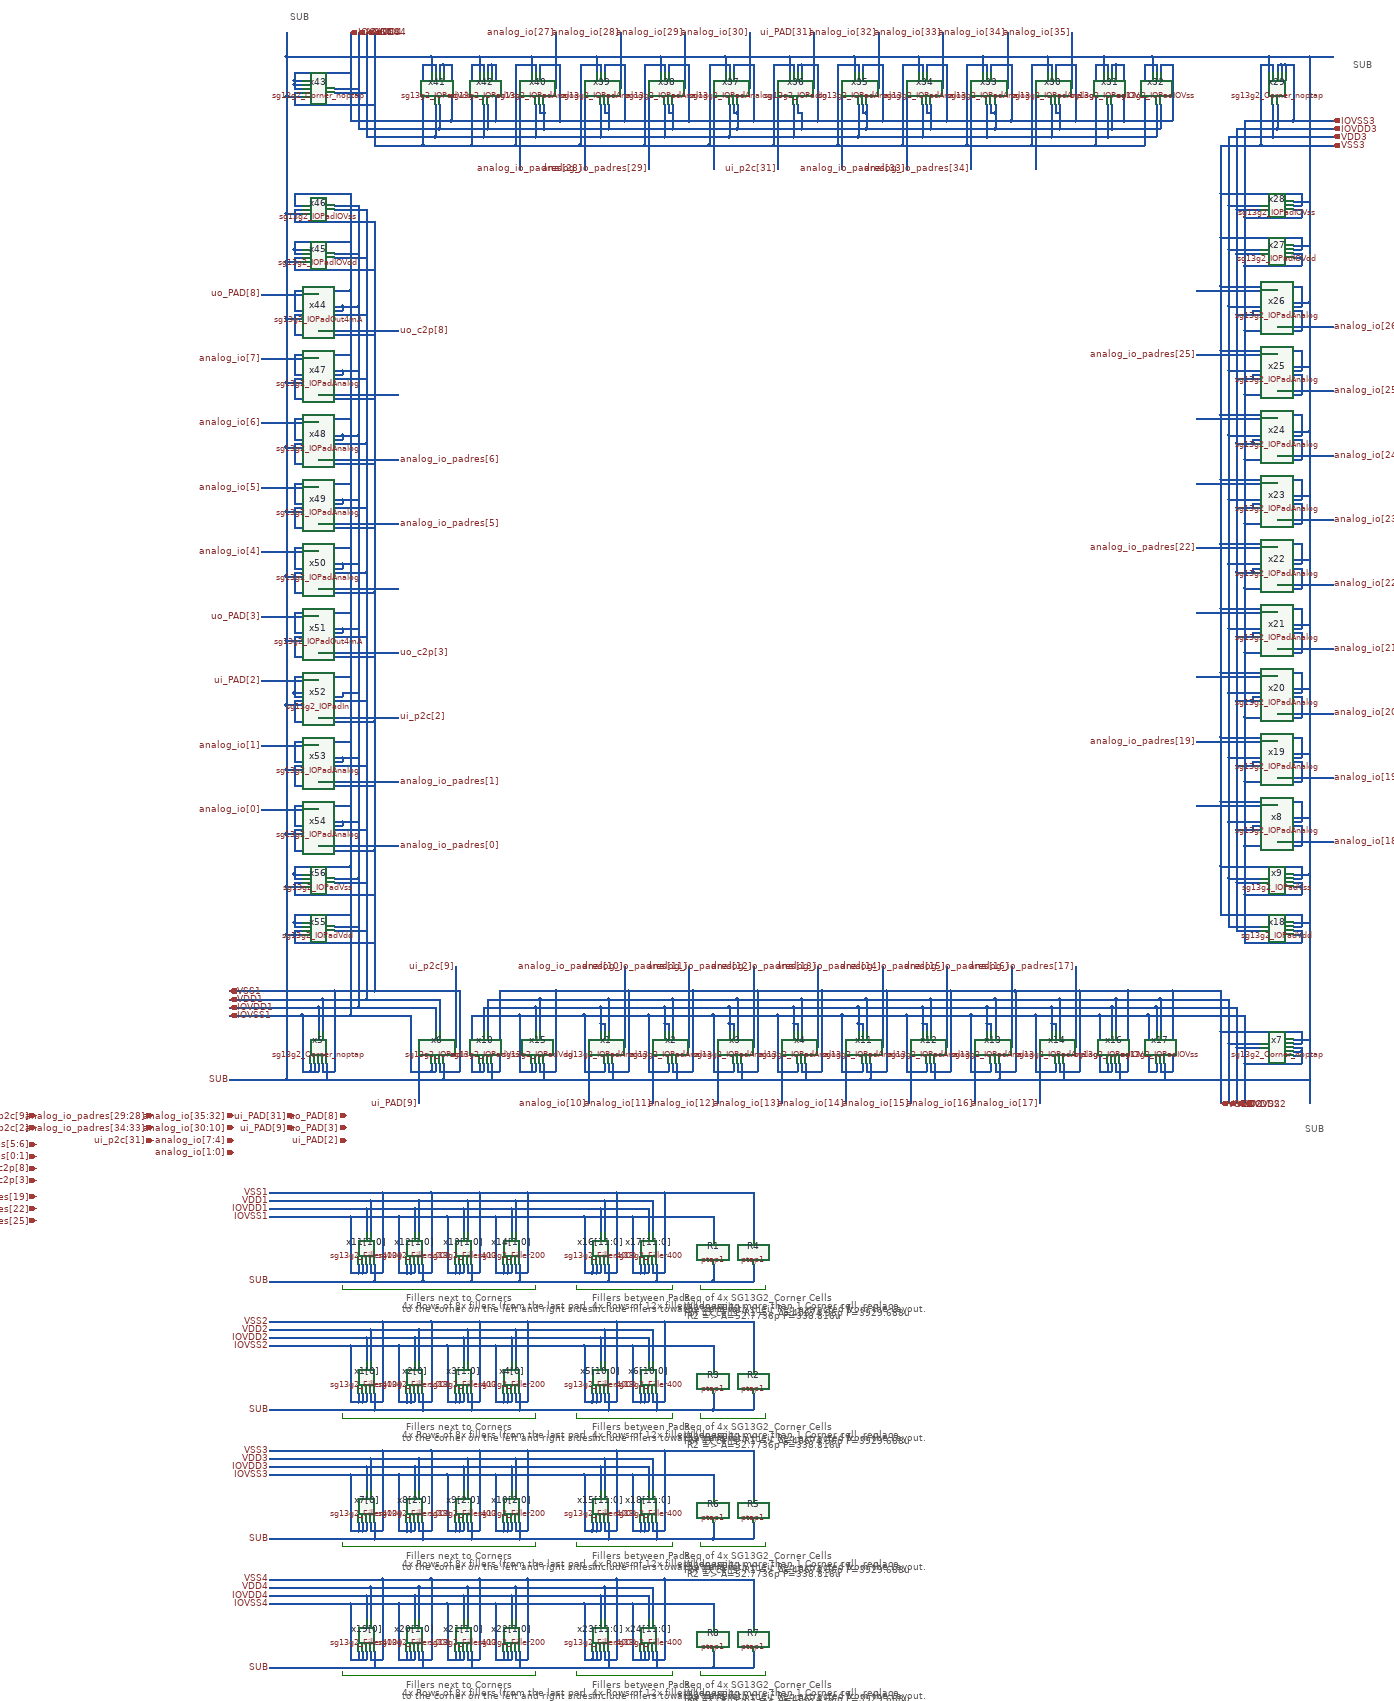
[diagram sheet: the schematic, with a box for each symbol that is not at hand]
v {xschem version=3.4.6 file_version=1.2}
G {}
K {}
V {}
S {}
E {}
L 4 1230 430 1230 440 {}
L 4 1230 440 1390 440 {}
L 4 1390 430 1390 440 {}
L 4 920 430 920 440 {}
L 4 920 440 1160 440 {}
L 4 1160 430 1160 440 {}
L 4 340 430 340 440 {}
L 4 340 440 820 440 {}
L 4 820 430 820 440 {}
L 4 1230 750 1230 760 {}
L 4 1230 760 1390 760 {}
L 4 1390 750 1390 760 {}
L 4 920 750 920 760 {}
L 4 920 760 1160 760 {}
L 4 1160 750 1160 760 {}
L 4 340 750 340 760 {}
L 4 340 760 820 760 {}
L 4 820 750 820 760 {}
L 4 1230 1070 1230 1080 {}
L 4 1230 1080 1390 1080 {}
L 4 1390 1070 1390 1080 {}
L 4 920 1070 920 1080 {}
L 4 920 1080 1160 1080 {}
L 4 1160 1070 1160 1080 {}
L 4 340 1070 340 1080 {}
L 4 340 1080 820 1080 {}
L 4 820 1070 820 1080 {}
L 4 1230 1390 1230 1400 {}
L 4 1230 1400 1390 1400 {}
L 4 1390 1390 1390 1400 {}
L 4 920 1390 920 1400 {}
L 4 920 1400 1160 1400 {}
L 4 1160 1390 1160 1400 {}
L 4 340 1390 340 1400 {}
L 4 340 1400 820 1400 {}
L 4 820 1390 820 1400 {}
T {SUB} 2730 30 3 0 0.3 0.3 {}
T {SUB} 2850 -2610 2 0 0.3 0.3 {}
T {SUB} 210 -2730 1 0 0.3 0.3 {}
T {Req of 4x SG13G2_Corner Cells} 1190 450 0 0 0.3 0.3 {}
T {When using more than 1 Corner cell, replace
the cells with their Req extracted from the Layout.
For 4x cells: R1 => A=40674.96p P=3929.688u
              R2 => A=52.7736p P=338.816u} 1190 470 0 0 0.2 0.2 {}
T {Fillers between Pads} 960 450 0 0 0.3 0.3 {}
T {4x Rows of 12x fillers (doesn't
include fillers towards corners).} 960 470 0 0 0.2 0.2 {}
T {Fillers next to Corners} 500 450 0 0 0.3 0.3 {}
T {4x Rows of 8x fillers (from the last pad
to the corner on the left and right sides).} 490 470 0 0 0.2 0.2 {}
T {Req of 4x SG13G2_Corner Cells} 1190 770 0 0 0.3 0.3 {}
T {When using more than 1 Corner cell, replace
the cells with their Req extracted from the Layout.
For 4x cells: R1 => A=40674.96p P=3929.688u
              R2 => A=52.7736p P=338.816u} 1190 790 0 0 0.2 0.2 {}
T {Fillers between Pads} 960 770 0 0 0.3 0.3 {}
T {4x Rows of 12x fillers (doesn't
include fillers towards corners).} 960 790 0 0 0.2 0.2 {}
T {Fillers next to Corners} 500 770 0 0 0.3 0.3 {}
T {4x Rows of 8x fillers (from the last pad
to the corner on the left and right sides).} 490 790 0 0 0.2 0.2 {}
T {Req of 4x SG13G2_Corner Cells} 1190 1090 0 0 0.3 0.3 {}
T {When using more than 1 Corner cell, replace
the cells with their Req extracted from the Layout.
For 4x cells: R1 => A=40674.96p P=3929.688u
              R2 => A=52.7736p P=338.816u} 1190 1110 0 0 0.2 0.2 {}
T {Fillers between Pads} 960 1090 0 0 0.3 0.3 {}
T {4x Rows of 12x fillers (doesn't
include fillers towards corners).} 960 1110 0 0 0.2 0.2 {}
T {Fillers next to Corners} 500 1090 0 0 0.3 0.3 {}
T {4x Rows of 8x fillers (from the last pad
to the corner on the left and right sides).} 490 1110 0 0 0.2 0.2 {}
T {Req of 4x SG13G2_Corner Cells} 1190 1410 0 0 0.3 0.3 {}
T {When using more than 1 Corner cell, replace
the cells with their Req extracted from the Layout.
For 4x cells: R1 => A=40674.96p P=3929.688u
              R2 => A=52.7736p P=338.816u} 1190 1430 0 0 0.2 0.2 {}
T {Fillers between Pads} 960 1410 0 0 0.3 0.3 {}
T {4x Rows of 12x fillers (doesn't
include fillers towards corners).} 960 1430 0 0 0.2 0.2 {}
T {Fillers next to Corners} 500 1410 0 0 0.3 0.3 {}
T {4x Rows of 8x fillers (from the last pad
to the corner on the left and right sides).} 490 1430 0 0 0.2 0.2 {}
N 60 -300 320 -300 {lab=VSS1}
N 60 -280 290 -280 {lab=VDD1}
N 60 -260 280 -260 {lab=IOVDD1}
N 60 -240 240 -240 {lab=IOVSS1}
N 200 -80 300 -80 {lab=SUB}
N 300 -120 300 -80 {lab=SUB}
N 260 -120 260 -100 {lab=IOVSS1}
N 270 -120 270 -100 {lab=IOVSS1}
N 260 -100 270 -100 {lab=IOVSS1}
N 290 -120 290 -100 {lab=VSS1}
N 290 -100 320 -100 {lab=VSS1}
N 320 -300 320 -100 {lab=VSS1}
N 290 -280 290 -200 {lab=VDD1}
N 280 -260 280 -200 {lab=IOVDD1}
N 240 -100 260 -100 {lab=IOVSS1}
N 240 -240 240 -100 {lab=IOVSS1}
N 280 -120 280 -100 {lab=IOVSS1}
N 270 -100 280 -100 {lab=IOVSS1}
N 580 -120 580 -100 {lab=VSS1}
N 580 -100 630 -100 {lab=VSS1}
N 630 -300 630 -100 {lab=VSS1}
N 580 -280 580 -200 {lab=VDD1}
N 570 -260 570 -200 {lab=IOVDD1}
N 420 -300 630 -300 {lab=VSS1}
N 400 -280 580 -280 {lab=VDD1}
N 380 -260 570 -260 {lab=IOVDD1}
N 560 -120 560 -100 {lab=IOVSS1}
N 570 -120 570 -100 {lab=IOVSS1}
N 560 -100 570 -100 {lab=IOVSS1}
N 510 -100 560 -100 {lab=IOVSS1}
N 510 -240 510 -100 {lab=IOVSS1}
N 360 -240 510 -240 {lab=IOVSS1}
N 700 -120 700 -100 {lab=VSS2}
N 700 -100 730 -100 {lab=VSS2}
N 730 -300 730 -100 {lab=VSS2}
N 700 -280 700 -200 {lab=VDD2}
N 690 -260 690 -200 {lab=IOVDD2}
N 680 -120 680 -100 {lab=IOVSS2}
N 690 -120 690 -100 {lab=IOVSS2}
N 680 -100 690 -100 {lab=IOVSS2}
N 660 -100 680 -100 {lab=IOVSS2}
N 660 -240 660 -100 {lab=IOVSS2}
N 2260 -120 2260 -100 {lab=VSS2}
N 2260 -100 2290 -100 {lab=VSS2}
N 2290 -300 2290 -100 {lab=VSS2}
N 2260 -280 2260 -200 {lab=VDD2}
N 2250 -260 2250 -200 {lab=IOVDD2}
N 2240 -120 2240 -100 {lab=IOVSS2}
N 2250 -120 2250 -100 {lab=IOVSS2}
N 2240 -100 2250 -100 {lab=IOVSS2}
N 2220 -100 2240 -100 {lab=IOVSS2}
N 2220 -240 2220 -100 {lab=IOVSS2}
N 2170 -300 2290 -300 {lab=VSS2}
N 2120 -280 2260 -280 {lab=VDD2}
N 2100 -260 2250 -260 {lab=IOVDD2}
N 2060 -240 2220 -240 {lab=IOVSS2}
N 2370 -120 2370 -100 {lab=VSS2}
N 2370 -100 2400 -100 {lab=VSS2}
N 2400 -300 2400 -100 {lab=VSS2}
N 2360 -260 2360 -200 {lab=IOVDD2}
N 2360 -120 2360 -100 {lab=IOVSS2}
N 2340 -240 2340 -100 {lab=IOVSS2}
N 2290 -300 2400 -300 {lab=VSS2}
N 2250 -260 2360 -260 {lab=IOVDD2}
N 2220 -240 2340 -240 {lab=IOVSS2}
N 2340 -100 2360 -100 {lab=IOVSS2}
N 620 -360 620 -160 {lab=ui_p2c[9]}
N 530 -160 530 -20 {lab=ui_PAD[9]}
N 830 -120 830 -100 {lab=VSS2}
N 830 -100 870 -100 {lab=VSS2}
N 780 -240 940 -240 {lab=IOVSS2}
N 840 -120 840 -80 {lab=SUB}
N 870 -300 1050 -300 {lab=VSS2}
N 690 -260 820 -260 {lab=IOVDD2}
N 820 -260 820 -200 {lab=IOVDD2}
N 830 -280 1000 -280 {lab=VDD2}
N 1040 -360 1040 -160 {lab=analog_io_padres[10]}
N 950 -160 950 -20 {lab=analog_io[10]}
N 990 -120 990 -100 {lab=IOVSS2}
N 940 -100 990 -100 {lab=IOVSS2}
N 940 -240 940 -100 {lab=IOVSS2}
N 1000 -120 1000 -100 {lab=VSS2}
N 1000 -100 1050 -100 {lab=VSS2}
N 1050 -300 1050 -100 {lab=VSS2}
N 980 -220 980 -200 {lab=IOVDD2}
N 990 -220 990 -200 {lab=IOVDD2}
N 980 -220 990 -220 {lab=IOVDD2}
N 980 -260 980 -220 {lab=IOVDD2}
N 1000 -280 1000 -200 {lab=VDD2}
N 820 -260 980 -260 {lab=IOVDD2}
N 1200 -360 1200 -160 {lab=#net1}
N 1110 -160 1110 -20 {lab=analog_io[11]}
N 1150 -120 1150 -100 {lab=IOVSS2}
N 1100 -100 1150 -100 {lab=IOVSS2}
N 1100 -240 1100 -100 {lab=IOVSS2}
N 1160 -120 1160 -100 {lab=VSS2}
N 1160 -100 1210 -100 {lab=VSS2}
N 1210 -300 1210 -100 {lab=VSS2}
N 1140 -220 1140 -200 {lab=IOVDD2}
N 1150 -220 1150 -200 {lab=IOVDD2}
N 1140 -220 1150 -220 {lab=IOVDD2}
N 1140 -260 1140 -220 {lab=IOVDD2}
N 1160 -280 1160 -200 {lab=VDD2}
N 940 -240 1100 -240 {lab=IOVSS2}
N 1050 -300 1210 -300 {lab=VSS2}
N 980 -260 1140 -260 {lab=IOVDD2}
N 1000 -280 1160 -280 {lab=VDD2}
N 1360 -360 1360 -160 {lab=#net2}
N 1270 -160 1270 -20 {lab=analog_io[12]}
N 1310 -120 1310 -100 {lab=IOVSS2}
N 1260 -100 1310 -100 {lab=IOVSS2}
N 1260 -240 1260 -100 {lab=IOVSS2}
N 1320 -120 1320 -100 {lab=VSS2}
N 1320 -100 1370 -100 {lab=VSS2}
N 1370 -300 1370 -100 {lab=VSS2}
N 1300 -220 1300 -200 {lab=IOVDD2}
N 1310 -220 1310 -200 {lab=IOVDD2}
N 1300 -220 1310 -220 {lab=IOVDD2}
N 1300 -260 1300 -220 {lab=IOVDD2}
N 1320 -280 1320 -200 {lab=VDD2}
N 1100 -240 1260 -240 {lab=IOVSS2}
N 1210 -300 1370 -300 {lab=VSS2}
N 1140 -260 1300 -260 {lab=IOVDD2}
N 1160 -280 1320 -280 {lab=VDD2}
N 1520 -360 1520 -160 {lab=#net3}
N 1430 -160 1430 -20 {lab=analog_io[13]}
N 1470 -120 1470 -100 {lab=IOVSS2}
N 1420 -100 1470 -100 {lab=IOVSS2}
N 1420 -240 1420 -100 {lab=IOVSS2}
N 1480 -120 1480 -100 {lab=VSS2}
N 1480 -100 1530 -100 {lab=VSS2}
N 1530 -300 1530 -100 {lab=VSS2}
N 1460 -220 1460 -200 {lab=IOVDD2}
N 1470 -220 1470 -200 {lab=IOVDD2}
N 1460 -220 1470 -220 {lab=IOVDD2}
N 1460 -260 1460 -220 {lab=IOVDD2}
N 1480 -280 1480 -200 {lab=VDD2}
N 1260 -240 1420 -240 {lab=IOVSS2}
N 1370 -300 1530 -300 {lab=VSS2}
N 1300 -260 1460 -260 {lab=IOVDD2}
N 1320 -280 1480 -280 {lab=VDD2}
N 1680 -360 1680 -160 {lab=#net4}
N 1590 -160 1590 -20 {lab=analog_io[14]}
N 1630 -120 1630 -100 {lab=IOVSS2}
N 1580 -100 1630 -100 {lab=IOVSS2}
N 1580 -240 1580 -100 {lab=IOVSS2}
N 1640 -120 1640 -100 {lab=VSS2}
N 1640 -100 1690 -100 {lab=VSS2}
N 1690 -300 1690 -100 {lab=VSS2}
N 1620 -220 1620 -200 {lab=IOVDD2}
N 1630 -220 1630 -200 {lab=IOVDD2}
N 1620 -220 1630 -220 {lab=IOVDD2}
N 1620 -260 1620 -220 {lab=IOVDD2}
N 1640 -280 1640 -200 {lab=VDD2}
N 1420 -240 1580 -240 {lab=IOVSS2}
N 1530 -300 1690 -300 {lab=VSS2}
N 1460 -260 1620 -260 {lab=IOVDD2}
N 1480 -280 1640 -280 {lab=VDD2}
N 1840 -360 1840 -160 {lab=#net5}
N 1750 -160 1750 -20 {lab=analog_io[15]}
N 1790 -120 1790 -100 {lab=IOVSS2}
N 1740 -100 1790 -100 {lab=IOVSS2}
N 1740 -240 1740 -100 {lab=IOVSS2}
N 1800 -120 1800 -100 {lab=VSS2}
N 1800 -100 1850 -100 {lab=VSS2}
N 1850 -300 1850 -100 {lab=VSS2}
N 1780 -220 1780 -200 {lab=IOVDD2}
N 1790 -220 1790 -200 {lab=IOVDD2}
N 1780 -220 1790 -220 {lab=IOVDD2}
N 1800 -280 1800 -200 {lab=VDD2}
N 1580 -240 1740 -240 {lab=IOVSS2}
N 1690 -300 1850 -300 {lab=VSS2}
N 1780 -260 1940 -260 {lab=IOVDD2}
N 1640 -280 1800 -280 {lab=VDD2}
N 2000 -360 2000 -160 {lab=#net6}
N 1910 -160 1910 -20 {lab=analog_io[16]}
N 1950 -120 1950 -100 {lab=IOVSS2}
N 1900 -100 1950 -100 {lab=IOVSS2}
N 1900 -240 1900 -100 {lab=IOVSS2}
N 1960 -120 1960 -100 {lab=VSS2}
N 1960 -100 2010 -100 {lab=VSS2}
N 2010 -300 2010 -100 {lab=VSS2}
N 1940 -220 1940 -200 {lab=IOVDD2}
N 1950 -220 1950 -200 {lab=IOVDD2}
N 1940 -220 1950 -220 {lab=IOVDD2}
N 1940 -260 1940 -220 {lab=IOVDD2}
N 1960 -280 1960 -200 {lab=VDD2}
N 1740 -240 1900 -240 {lab=IOVSS2}
N 1850 -300 2010 -300 {lab=VSS2}
N 1800 -280 1960 -280 {lab=VDD2}
N 2160 -360 2160 -160 {lab=#net7}
N 2070 -160 2070 -20 {lab=analog_io[17]}
N 2110 -120 2110 -100 {lab=IOVSS2}
N 2060 -100 2110 -100 {lab=IOVSS2}
N 2060 -240 2060 -100 {lab=IOVSS2}
N 2120 -120 2120 -100 {lab=VSS2}
N 2120 -100 2170 -100 {lab=VSS2}
N 2170 -300 2170 -100 {lab=VSS2}
N 2100 -220 2100 -200 {lab=IOVDD2}
N 2110 -220 2110 -200 {lab=IOVDD2}
N 2100 -220 2110 -220 {lab=IOVDD2}
N 2100 -260 2100 -220 {lab=IOVDD2}
N 2120 -280 2120 -200 {lab=VDD2}
N 1900 -240 2060 -240 {lab=IOVSS2}
N 2010 -300 2170 -300 {lab=VSS2}
N 1940 -260 2100 -260 {lab=IOVDD2}
N 1960 -280 2120 -280 {lab=VDD2}
N 160 200 440 200 {lab=VSS1}
N 160 220 410 220 {lab=VDD1}
N 160 240 400 240 {lab=IOVDD1}
N 160 260 360 260 {lab=IOVSS1}
N 160 420 420 420 {lab=SUB}
N 420 380 420 420 {lab=SUB}
N 380 380 380 400 {lab=IOVSS1}
N 390 380 390 400 {lab=IOVSS1}
N 380 400 390 400 {lab=IOVSS1}
N 410 380 410 400 {lab=VSS1}
N 410 400 440 400 {lab=VSS1}
N 440 200 440 400 {lab=VSS1}
N 410 220 410 300 {lab=VDD1}
N 400 240 400 300 {lab=IOVDD1}
N 360 400 380 400 {lab=IOVSS1}
N 360 260 360 400 {lab=IOVSS1}
N 400 380 400 400 {lab=IOVSS1}
N 390 400 400 400 {lab=IOVSS1}
N 500 380 500 400 {lab=IOVSS1}
N 510 380 510 400 {lab=IOVSS1}
N 500 400 510 400 {lab=IOVSS1}
N 530 380 530 400 {lab=VSS1}
N 530 400 560 400 {lab=VSS1}
N 560 200 560 400 {lab=VSS1}
N 530 220 530 300 {lab=VDD1}
N 520 240 520 300 {lab=IOVDD1}
N 480 400 500 400 {lab=IOVSS1}
N 480 260 480 400 {lab=IOVSS1}
N 520 380 520 400 {lab=IOVSS1}
N 510 400 520 400 {lab=IOVSS1}
N 440 200 560 200 {lab=VSS1}
N 410 220 530 220 {lab=VDD1}
N 400 240 520 240 {lab=IOVDD1}
N 360 260 480 260 {lab=IOVSS1}
N 620 380 620 400 {lab=IOVSS1}
N 630 380 630 400 {lab=IOVSS1}
N 620 400 630 400 {lab=IOVSS1}
N 650 380 650 400 {lab=VSS1}
N 650 400 680 400 {lab=VSS1}
N 680 200 680 400 {lab=VSS1}
N 650 220 650 300 {lab=VDD1}
N 640 240 640 300 {lab=IOVDD1}
N 600 400 620 400 {lab=IOVSS1}
N 600 260 600 400 {lab=IOVSS1}
N 640 380 640 400 {lab=IOVSS1}
N 630 400 640 400 {lab=IOVSS1}
N 560 200 680 200 {lab=VSS1}
N 530 220 650 220 {lab=VDD1}
N 520 240 640 240 {lab=IOVDD1}
N 480 260 600 260 {lab=IOVSS1}
N 740 380 740 400 {lab=IOVSS1}
N 750 380 750 400 {lab=IOVSS1}
N 740 400 750 400 {lab=IOVSS1}
N 770 380 770 400 {lab=VSS1}
N 770 400 800 400 {lab=VSS1}
N 800 200 800 400 {lab=VSS1}
N 770 220 770 300 {lab=VDD1}
N 760 240 760 300 {lab=IOVDD1}
N 720 400 740 400 {lab=IOVSS1}
N 720 260 720 400 {lab=IOVSS1}
N 760 380 760 400 {lab=IOVSS1}
N 750 400 760 400 {lab=IOVSS1}
N 680 200 800 200 {lab=VSS1}
N 650 220 770 220 {lab=VDD1}
N 640 240 760 240 {lab=IOVDD1}
N 600 260 720 260 {lab=IOVSS1}
N 960 380 960 400 {lab=IOVSS1}
N 970 380 970 400 {lab=IOVSS1}
N 960 400 970 400 {lab=IOVSS1}
N 990 380 990 400 {lab=VSS1}
N 990 400 1020 400 {lab=VSS1}
N 1020 200 1020 400 {lab=VSS1}
N 990 220 990 300 {lab=VDD1}
N 980 240 980 300 {lab=IOVDD1}
N 940 400 960 400 {lab=IOVSS1}
N 940 260 940 400 {lab=IOVSS1}
N 980 380 980 400 {lab=IOVSS1}
N 970 400 980 400 {lab=IOVSS1}
N 800 200 1020 200 {lab=VSS1}
N 770 220 990 220 {lab=VDD1}
N 760 240 980 240 {lab=IOVDD1}
N 720 260 940 260 {lab=IOVSS1}
N 1080 380 1080 400 {lab=IOVSS1}
N 1090 380 1090 400 {lab=IOVSS1}
N 1080 400 1090 400 {lab=IOVSS1}
N 1110 380 1110 400 {lab=VSS1}
N 1110 400 1140 400 {lab=VSS1}
N 1140 200 1140 400 {lab=VSS1}
N 1110 220 1110 300 {lab=VDD1}
N 1100 240 1100 300 {lab=IOVDD1}
N 1060 400 1080 400 {lab=IOVSS1}
N 1060 260 1060 400 {lab=IOVSS1}
N 1100 380 1100 400 {lab=IOVSS1}
N 1090 400 1100 400 {lab=IOVSS1}
N 1020 200 1140 200 {lab=VSS1}
N 990 220 1110 220 {lab=VDD1}
N 980 240 1100 240 {lab=IOVDD1}
N 940 260 1060 260 {lab=IOVSS1}
N 1000 420 1120 420 {lab=SUB}
N 1120 380 1120 420 {lab=SUB}
N 1000 380 1000 420 {lab=SUB}
N 780 420 1000 420 {lab=SUB}
N 780 380 780 420 {lab=SUB}
N 660 420 780 420 {lab=SUB}
N 660 380 660 420 {lab=SUB}
N 540 420 660 420 {lab=SUB}
N 540 380 540 420 {lab=SUB}
N 420 420 540 420 {lab=SUB}
N 2270 -80 2380 -80 {lab=SUB}
N 2380 -120 2380 -80 {lab=SUB}
N 2270 -120 2270 -80 {lab=SUB}
N 2130 -80 2270 -80 {lab=SUB}
N 2130 -120 2130 -80 {lab=SUB}
N 1970 -80 2130 -80 {lab=SUB}
N 1970 -120 1970 -80 {lab=SUB}
N 1810 -80 1970 -80 {lab=SUB}
N 1810 -120 1810 -80 {lab=SUB}
N 1650 -80 1810 -80 {lab=SUB}
N 1650 -120 1650 -80 {lab=SUB}
N 1490 -80 1650 -80 {lab=SUB}
N 1490 -120 1490 -80 {lab=SUB}
N 1330 -80 1490 -80 {lab=SUB}
N 1330 -120 1330 -80 {lab=SUB}
N 1170 -80 1330 -80 {lab=SUB}
N 1170 -120 1170 -80 {lab=SUB}
N 1010 -80 1170 -80 {lab=SUB}
N 1010 -120 1010 -80 {lab=SUB}
N 840 -80 1010 -80 {lab=SUB}
N 710 -120 710 -80 {lab=SUB}
N 590 -80 710 -80 {lab=SUB}
N 590 -120 590 -80 {lab=SUB}
N 300 -80 590 -80 {lab=SUB}
N 2370 -280 2370 -200 {lab=VDD2}
N 2260 -280 2370 -280 {lab=VDD2}
N 1780 -260 1780 -220 {lab=IOVDD2}
N 1620 -260 1780 -260 {lab=IOVDD2}
N 2520 -200 2520 -20 {lab=VSS2}
N 2540 -170 2540 -20 {lab=VDD2}
N 2560 -160 2560 -20 {lab=IOVDD2}
N 2580 -120 2580 -20 {lab=IOVSS2}
N 2740 -80 2740 -20 {lab=SUB}
N 2700 -180 2740 -180 {lab=SUB}
N 2700 -140 2720 -140 {lab=IOVSS2}
N 2700 -150 2720 -150 {lab=IOVSS2}
N 2720 -150 2720 -140 {lab=IOVSS2}
N 2700 -170 2720 -170 {lab=VSS2}
N 2720 -200 2720 -170 {lab=VSS2}
N 2520 -200 2720 -200 {lab=VSS2}
N 2540 -170 2620 -170 {lab=VDD2}
N 2560 -160 2620 -160 {lab=IOVDD2}
N 2720 -140 2720 -120 {lab=IOVSS2}
N 2580 -120 2720 -120 {lab=IOVSS2}
N 2700 -160 2720 -160 {lab=IOVSS2}
N 2720 -160 2720 -150 {lab=IOVSS2}
N 2700 -460 2720 -460 {lab=VSS3}
N 2720 -490 2720 -460 {lab=VSS3}
N 2520 -490 2720 -490 {lab=VSS3}
N 2540 -460 2620 -460 {lab=VDD3}
N 2560 -450 2620 -450 {lab=IOVDD3}
N 2520 -300 2520 -200 {lab=VSS2}
N 2540 -280 2540 -170 {lab=VDD2}
N 2560 -260 2560 -160 {lab=IOVDD2}
N 2700 -440 2720 -440 {lab=IOVSS3}
N 2700 -450 2720 -450 {lab=IOVSS3}
N 2720 -450 2720 -440 {lab=IOVSS3}
N 2720 -440 2720 -420 {lab=IOVSS3}
N 2580 -420 2720 -420 {lab=IOVSS3}
N 2580 -240 2580 -120 {lab=IOVSS2}
N 2700 -580 2720 -580 {lab=VSS3}
N 2720 -610 2720 -580 {lab=VSS3}
N 2520 -610 2720 -610 {lab=VSS3}
N 2540 -580 2620 -580 {lab=VDD3}
N 2560 -570 2620 -570 {lab=IOVDD3}
N 2700 -560 2720 -560 {lab=IOVSS3}
N 2700 -570 2720 -570 {lab=IOVSS3}
N 2720 -570 2720 -560 {lab=IOVSS3}
N 2720 -560 2720 -540 {lab=IOVSS3}
N 2580 -540 2720 -540 {lab=IOVSS3}
N 2520 -610 2520 -490 {lab=VSS3}
N 2540 -580 2540 -460 {lab=VDD3}
N 2560 -570 2560 -450 {lab=IOVDD3}
N 2580 -540 2580 -420 {lab=IOVSS3}
N 2700 -2140 2720 -2140 {lab=VSS3}
N 2720 -2170 2720 -2140 {lab=VSS3}
N 2520 -2170 2720 -2170 {lab=VSS3}
N 2540 -2140 2620 -2140 {lab=VDD3}
N 2560 -2130 2620 -2130 {lab=IOVDD3}
N 2700 -2120 2720 -2120 {lab=IOVSS3}
N 2700 -2130 2720 -2130 {lab=IOVSS3}
N 2720 -2130 2720 -2120 {lab=IOVSS3}
N 2720 -2120 2720 -2100 {lab=IOVSS3}
N 2580 -2100 2720 -2100 {lab=IOVSS3}
N 2520 -2170 2520 -2050 {lab=VSS3}
N 2540 -2140 2540 -2000 {lab=VDD3}
N 2560 -2130 2560 -1980 {lab=IOVDD3}
N 2580 -2100 2580 -1940 {lab=IOVSS3}
N 2700 -2250 2720 -2250 {lab=VSS3}
N 2720 -2280 2720 -2250 {lab=VSS3}
N 2520 -2280 2720 -2280 {lab=VSS3}
N 2560 -2240 2620 -2240 {lab=IOVDD3}
N 2700 -2240 2720 -2240 {lab=IOVSS3}
N 2580 -2220 2720 -2220 {lab=IOVSS3}
N 2520 -2280 2520 -2170 {lab=VSS3}
N 2560 -2240 2560 -2130 {lab=IOVDD3}
N 2580 -2220 2580 -2100 {lab=IOVSS3}
N 2720 -2240 2720 -2220 {lab=IOVSS3}
N 2460 -760 2660 -760 {lab=#net8}
N 2660 -670 2800 -670 {lab=analog_io[18]}
N 2700 -710 2720 -710 {lab=IOVSS3}
N 2720 -710 2720 -660 {lab=IOVSS3}
N 2580 -660 2720 -660 {lab=IOVSS3}
N 2580 -660 2580 -540 {lab=IOVSS3}
N 2700 -720 2720 -720 {lab=VSS3}
N 2720 -770 2720 -720 {lab=VSS3}
N 2520 -770 2720 -770 {lab=VSS3}
N 2520 -770 2520 -610 {lab=VSS3}
N 2600 -700 2620 -700 {lab=IOVDD3}
N 2560 -700 2560 -570 {lab=IOVDD3}
N 2600 -710 2620 -710 {lab=IOVDD3}
N 2600 -710 2600 -700 {lab=IOVDD3}
N 2560 -700 2600 -700 {lab=IOVDD3}
N 2540 -720 2620 -720 {lab=VDD3}
N 2540 -720 2540 -580 {lab=VDD3}
N 2460 -920 2660 -920 {lab=analog_io_padres[19]}
N 2660 -830 2800 -830 {lab=analog_io[19]}
N 2700 -870 2720 -870 {lab=IOVSS3}
N 2720 -870 2720 -820 {lab=IOVSS3}
N 2580 -820 2720 -820 {lab=IOVSS3}
N 2700 -880 2720 -880 {lab=VSS3}
N 2720 -930 2720 -880 {lab=VSS3}
N 2520 -930 2720 -930 {lab=VSS3}
N 2600 -860 2620 -860 {lab=IOVDD3}
N 2600 -870 2620 -870 {lab=IOVDD3}
N 2600 -870 2600 -860 {lab=IOVDD3}
N 2560 -860 2600 -860 {lab=IOVDD3}
N 2540 -880 2620 -880 {lab=VDD3}
N 2580 -820 2580 -660 {lab=IOVSS3}
N 2520 -930 2520 -770 {lab=VSS3}
N 2560 -860 2560 -700 {lab=IOVDD3}
N 2540 -880 2540 -720 {lab=VDD3}
N 2460 -1080 2660 -1080 {lab=#net9}
N 2660 -990 2800 -990 {lab=analog_io[20]}
N 2700 -1030 2720 -1030 {lab=IOVSS3}
N 2720 -1030 2720 -980 {lab=IOVSS3}
N 2580 -980 2720 -980 {lab=IOVSS3}
N 2700 -1040 2720 -1040 {lab=VSS3}
N 2720 -1090 2720 -1040 {lab=VSS3}
N 2520 -1090 2720 -1090 {lab=VSS3}
N 2600 -1020 2620 -1020 {lab=IOVDD3}
N 2600 -1030 2620 -1030 {lab=IOVDD3}
N 2600 -1030 2600 -1020 {lab=IOVDD3}
N 2560 -1020 2600 -1020 {lab=IOVDD3}
N 2540 -1040 2620 -1040 {lab=VDD3}
N 2580 -980 2580 -820 {lab=IOVSS3}
N 2520 -1090 2520 -930 {lab=VSS3}
N 2560 -1020 2560 -860 {lab=IOVDD3}
N 2540 -1040 2540 -880 {lab=VDD3}
N 2460 -1240 2660 -1240 {lab=#net10}
N 2660 -1150 2800 -1150 {lab=analog_io[21]}
N 2700 -1190 2720 -1190 {lab=IOVSS3}
N 2720 -1190 2720 -1140 {lab=IOVSS3}
N 2580 -1140 2720 -1140 {lab=IOVSS3}
N 2700 -1200 2720 -1200 {lab=VSS3}
N 2720 -1250 2720 -1200 {lab=VSS3}
N 2520 -1250 2720 -1250 {lab=VSS3}
N 2600 -1180 2620 -1180 {lab=IOVDD3}
N 2600 -1190 2620 -1190 {lab=IOVDD3}
N 2600 -1190 2600 -1180 {lab=IOVDD3}
N 2560 -1180 2600 -1180 {lab=IOVDD3}
N 2540 -1200 2620 -1200 {lab=VDD3}
N 2580 -1140 2580 -980 {lab=IOVSS3}
N 2520 -1250 2520 -1090 {lab=VSS3}
N 2560 -1180 2560 -1020 {lab=IOVDD3}
N 2540 -1200 2540 -1040 {lab=VDD3}
N 2460 -1400 2660 -1400 {lab=analog_io_padres[22]}
N 2660 -1310 2800 -1310 {lab=analog_io[22]}
N 2700 -1350 2720 -1350 {lab=IOVSS3}
N 2720 -1350 2720 -1300 {lab=IOVSS3}
N 2580 -1300 2720 -1300 {lab=IOVSS3}
N 2700 -1360 2720 -1360 {lab=VSS3}
N 2720 -1410 2720 -1360 {lab=VSS3}
N 2520 -1410 2720 -1410 {lab=VSS3}
N 2600 -1340 2620 -1340 {lab=IOVDD3}
N 2600 -1350 2620 -1350 {lab=IOVDD3}
N 2600 -1350 2600 -1340 {lab=IOVDD3}
N 2560 -1340 2600 -1340 {lab=IOVDD3}
N 2540 -1360 2620 -1360 {lab=VDD3}
N 2580 -1300 2580 -1140 {lab=IOVSS3}
N 2520 -1410 2520 -1250 {lab=VSS3}
N 2560 -1340 2560 -1180 {lab=IOVDD3}
N 2540 -1360 2540 -1200 {lab=VDD3}
N 2460 -1560 2660 -1560 {lab=#net11}
N 2660 -1470 2800 -1470 {lab=analog_io[23]}
N 2700 -1510 2720 -1510 {lab=IOVSS3}
N 2720 -1510 2720 -1460 {lab=IOVSS3}
N 2580 -1460 2720 -1460 {lab=IOVSS3}
N 2700 -1520 2720 -1520 {lab=VSS3}
N 2720 -1570 2720 -1520 {lab=VSS3}
N 2520 -1570 2720 -1570 {lab=VSS3}
N 2600 -1500 2620 -1500 {lab=IOVDD3}
N 2600 -1510 2620 -1510 {lab=IOVDD3}
N 2600 -1510 2600 -1500 {lab=IOVDD3}
N 2560 -1500 2600 -1500 {lab=IOVDD3}
N 2540 -1520 2620 -1520 {lab=VDD3}
N 2580 -1460 2580 -1300 {lab=IOVSS3}
N 2520 -1570 2520 -1410 {lab=VSS3}
N 2560 -1500 2560 -1340 {lab=IOVDD3}
N 2540 -1520 2540 -1360 {lab=VDD3}
N 2460 -1720 2660 -1720 {lab=#net12}
N 2660 -1630 2800 -1630 {lab=analog_io[24]}
N 2700 -1670 2720 -1670 {lab=IOVSS3}
N 2720 -1670 2720 -1620 {lab=IOVSS3}
N 2580 -1620 2720 -1620 {lab=IOVSS3}
N 2700 -1680 2720 -1680 {lab=VSS3}
N 2720 -1730 2720 -1680 {lab=VSS3}
N 2520 -1730 2720 -1730 {lab=VSS3}
N 2600 -1660 2620 -1660 {lab=IOVDD3}
N 2600 -1670 2620 -1670 {lab=IOVDD3}
N 2600 -1670 2600 -1660 {lab=IOVDD3}
N 2540 -1680 2620 -1680 {lab=VDD3}
N 2580 -1620 2580 -1460 {lab=IOVSS3}
N 2520 -1730 2520 -1570 {lab=VSS3}
N 2560 -1820 2560 -1660 {lab=IOVDD3}
N 2540 -1680 2540 -1520 {lab=VDD3}
N 2460 -1880 2660 -1880 {lab=analog_io_padres[25]}
N 2660 -1790 2800 -1790 {lab=analog_io[25]}
N 2700 -1830 2720 -1830 {lab=IOVSS3}
N 2720 -1830 2720 -1780 {lab=IOVSS3}
N 2580 -1780 2720 -1780 {lab=IOVSS3}
N 2700 -1840 2720 -1840 {lab=VSS3}
N 2720 -1890 2720 -1840 {lab=VSS3}
N 2520 -1890 2720 -1890 {lab=VSS3}
N 2600 -1820 2620 -1820 {lab=IOVDD3}
N 2600 -1830 2620 -1830 {lab=IOVDD3}
N 2600 -1830 2600 -1820 {lab=IOVDD3}
N 2560 -1820 2600 -1820 {lab=IOVDD3}
N 2540 -1840 2620 -1840 {lab=VDD3}
N 2580 -1780 2580 -1620 {lab=IOVSS3}
N 2520 -1890 2520 -1730 {lab=VSS3}
N 2540 -1840 2540 -1680 {lab=VDD3}
N 2460 -2040 2660 -2040 {lab=#net13}
N 2660 -1950 2800 -1950 {lab=analog_io[26]}
N 2700 -1990 2720 -1990 {lab=IOVSS3}
N 2720 -1990 2720 -1940 {lab=IOVSS3}
N 2580 -1940 2720 -1940 {lab=IOVSS3}
N 2700 -2000 2720 -2000 {lab=VSS3}
N 2720 -2050 2720 -2000 {lab=VSS3}
N 2520 -2050 2720 -2050 {lab=VSS3}
N 2600 -1980 2620 -1980 {lab=IOVDD3}
N 2600 -1990 2620 -1990 {lab=IOVDD3}
N 2600 -1990 2600 -1980 {lab=IOVDD3}
N 2560 -1980 2600 -1980 {lab=IOVDD3}
N 2540 -2000 2620 -2000 {lab=VDD3}
N 2580 -1940 2580 -1780 {lab=IOVSS3}
N 2520 -2050 2520 -1890 {lab=VSS3}
N 2560 -1980 2560 -1820 {lab=IOVDD3}
N 2540 -2000 2540 -1840 {lab=VDD3}
N 2740 -2260 2740 -2150 {lab=SUB}
N 2700 -2260 2740 -2260 {lab=SUB}
N 2700 -2150 2740 -2150 {lab=SUB}
N 2740 -2150 2740 -2010 {lab=SUB}
N 2700 -2010 2740 -2010 {lab=SUB}
N 2740 -2010 2740 -1850 {lab=SUB}
N 2700 -1850 2740 -1850 {lab=SUB}
N 2740 -1850 2740 -1690 {lab=SUB}
N 2700 -1690 2740 -1690 {lab=SUB}
N 2740 -1690 2740 -1530 {lab=SUB}
N 2700 -1530 2740 -1530 {lab=SUB}
N 2740 -1530 2740 -1370 {lab=SUB}
N 2700 -1370 2740 -1370 {lab=SUB}
N 2740 -1370 2740 -1210 {lab=SUB}
N 2700 -1210 2740 -1210 {lab=SUB}
N 2740 -1210 2740 -1050 {lab=SUB}
N 2700 -1050 2740 -1050 {lab=SUB}
N 2740 -1050 2740 -890 {lab=SUB}
N 2700 -890 2740 -890 {lab=SUB}
N 2740 -890 2740 -730 {lab=SUB}
N 2700 -730 2740 -730 {lab=SUB}
N 2740 -730 2740 -590 {lab=SUB}
N 2700 -590 2740 -590 {lab=SUB}
N 2740 -590 2740 -470 {lab=SUB}
N 2700 -470 2740 -470 {lab=SUB}
N 2740 -470 2740 -180 {lab=SUB}
N 2540 -2250 2620 -2250 {lab=VDD3}
N 2540 -2250 2540 -2140 {lab=VDD3}
N 2560 -1660 2600 -1660 {lab=IOVDD3}
N 2560 -1660 2560 -1500 {lab=IOVDD3}
N 2400 -300 2520 -300 {lab=VSS2}
N 2370 -280 2540 -280 {lab=VDD2}
N 2360 -260 2560 -260 {lab=IOVDD2}
N 2340 -240 2580 -240 {lab=IOVSS2}
N 2380 -80 2740 -80 {lab=SUB}
N 2740 -180 2740 -80 {lab=SUB}
N 2620 -2400 2800 -2400 {lab=VSS3}
N 2650 -2420 2800 -2420 {lab=VDD3}
N 2660 -2440 2800 -2440 {lab=IOVDD3}
N 2700 -2460 2800 -2460 {lab=IOVSS3}
N 2640 -2620 2640 -2580 {lab=SUB}
N 2680 -2600 2680 -2580 {lab=IOVSS3}
N 2670 -2600 2670 -2580 {lab=IOVSS3}
N 2670 -2600 2680 -2600 {lab=IOVSS3}
N 2650 -2600 2650 -2580 {lab=VSS3}
N 2620 -2600 2650 -2600 {lab=VSS3}
N 2620 -2600 2620 -2400 {lab=VSS3}
N 2650 -2500 2650 -2420 {lab=VDD3}
N 2660 -2500 2660 -2440 {lab=IOVDD3}
N 2680 -2600 2700 -2600 {lab=IOVSS3}
N 2700 -2600 2700 -2460 {lab=IOVSS3}
N 2660 -2600 2660 -2580 {lab=IOVSS3}
N 2660 -2600 2670 -2600 {lab=IOVSS3}
N 2360 -2600 2360 -2580 {lab=VSS4}
N 2330 -2600 2360 -2600 {lab=VSS4}
N 2330 -2600 2330 -2400 {lab=VSS4}
N 2360 -2500 2360 -2420 {lab=VDD4}
N 2370 -2500 2370 -2440 {lab=IOVDD4}
N 2370 -2600 2370 -2580 {lab=IOVSS4}
N 2370 -2600 2400 -2600 {lab=IOVSS4}
N 2400 -2600 2400 -2460 {lab=IOVSS4}
N 2240 -2600 2240 -2580 {lab=VSS4}
N 2210 -2600 2240 -2600 {lab=VSS4}
N 2210 -2600 2210 -2400 {lab=VSS4}
N 2240 -2500 2240 -2420 {lab=VDD4}
N 2250 -2500 2250 -2440 {lab=IOVDD4}
N 2260 -2600 2260 -2580 {lab=IOVSS4}
N 2250 -2600 2250 -2580 {lab=IOVSS4}
N 2250 -2600 2260 -2600 {lab=IOVSS4}
N 2260 -2600 2280 -2600 {lab=IOVSS4}
N 2280 -2600 2280 -2460 {lab=IOVSS4}
N 2210 -2400 2330 -2400 {lab=VSS4}
N 2240 -2420 2360 -2420 {lab=VDD4}
N 2250 -2440 2370 -2440 {lab=IOVDD4}
N 2280 -2460 2400 -2460 {lab=IOVSS4}
N 570 -2600 570 -2580 {lab=VSS4}
N 540 -2600 570 -2600 {lab=VSS4}
N 540 -2600 540 -2400 {lab=VSS4}
N 570 -2500 570 -2420 {lab=VDD4}
N 580 -2500 580 -2440 {lab=IOVDD4}
N 590 -2600 590 -2580 {lab=IOVSS4}
N 580 -2600 580 -2580 {lab=IOVSS4}
N 580 -2600 590 -2600 {lab=IOVSS4}
N 590 -2600 610 -2600 {lab=IOVSS4}
N 610 -2600 610 -2460 {lab=IOVSS4}
N 690 -2600 690 -2580 {lab=VSS4}
N 660 -2600 690 -2600 {lab=VSS4}
N 660 -2600 660 -2400 {lab=VSS4}
N 700 -2500 700 -2440 {lab=IOVDD4}
N 700 -2600 700 -2580 {lab=IOVSS4}
N 720 -2600 720 -2460 {lab=IOVSS4}
N 660 -2400 770 -2400 {lab=VSS4}
N 700 -2440 840 -2440 {lab=IOVDD4}
N 720 -2460 880 -2460 {lab=IOVSS4}
N 710 -2600 720 -2600 {lab=IOVSS4}
N 2060 -2540 2060 -2340 {lab=#net14}
N 2150 -2680 2150 -2540 {lab=analog_io[35]}
N 2110 -2600 2110 -2580 {lab=IOVSS4}
N 2110 -2600 2160 -2600 {lab=IOVSS4}
N 2160 -2600 2160 -2460 {lab=IOVSS4}
N 2160 -2460 2280 -2460 {lab=IOVSS4}
N 2100 -2600 2100 -2580 {lab=VSS4}
N 2050 -2600 2100 -2600 {lab=VSS4}
N 2050 -2600 2050 -2400 {lab=VSS4}
N 2050 -2400 2210 -2400 {lab=VSS4}
N 2120 -2500 2120 -2480 {lab=IOVDD4}
N 2120 -2440 2250 -2440 {lab=IOVDD4}
N 2110 -2500 2110 -2480 {lab=IOVDD4}
N 2110 -2480 2120 -2480 {lab=IOVDD4}
N 2120 -2480 2120 -2440 {lab=IOVDD4}
N 2100 -2500 2100 -2420 {lab=VDD4}
N 2100 -2420 2240 -2420 {lab=VDD4}
N 1900 -2540 1900 -2340 {lab=analog_io_padres[34]}
N 1990 -2680 1990 -2540 {lab=analog_io[34]}
N 1950 -2600 1950 -2580 {lab=IOVSS4}
N 1950 -2600 2000 -2600 {lab=IOVSS4}
N 2000 -2600 2000 -2460 {lab=IOVSS4}
N 1940 -2600 1940 -2580 {lab=VSS4}
N 1890 -2600 1940 -2600 {lab=VSS4}
N 1890 -2600 1890 -2400 {lab=VSS4}
N 1960 -2500 1960 -2480 {lab=IOVDD4}
N 1950 -2500 1950 -2480 {lab=IOVDD4}
N 1950 -2480 1960 -2480 {lab=IOVDD4}
N 1960 -2480 1960 -2440 {lab=IOVDD4}
N 1940 -2500 1940 -2420 {lab=VDD4}
N 2000 -2460 2160 -2460 {lab=IOVSS4}
N 1890 -2400 2050 -2400 {lab=VSS4}
N 1960 -2440 2120 -2440 {lab=IOVDD4}
N 1940 -2420 2100 -2420 {lab=VDD4}
N 1740 -2540 1740 -2340 {lab=analog_io_padres[33]}
N 1830 -2680 1830 -2540 {lab=analog_io[33]}
N 1790 -2600 1790 -2580 {lab=IOVSS4}
N 1790 -2600 1840 -2600 {lab=IOVSS4}
N 1840 -2600 1840 -2460 {lab=IOVSS4}
N 1780 -2600 1780 -2580 {lab=VSS4}
N 1730 -2600 1780 -2600 {lab=VSS4}
N 1730 -2600 1730 -2400 {lab=VSS4}
N 1800 -2500 1800 -2480 {lab=IOVDD4}
N 1790 -2500 1790 -2480 {lab=IOVDD4}
N 1790 -2480 1800 -2480 {lab=IOVDD4}
N 1800 -2480 1800 -2440 {lab=IOVDD4}
N 1780 -2500 1780 -2420 {lab=VDD4}
N 1840 -2460 2000 -2460 {lab=IOVSS4}
N 1730 -2400 1890 -2400 {lab=VSS4}
N 1800 -2440 1960 -2440 {lab=IOVDD4}
N 1780 -2420 1940 -2420 {lab=VDD4}
N 1580 -2540 1580 -2340 {lab=#net15}
N 1670 -2680 1670 -2540 {lab=analog_io[32]}
N 1630 -2600 1630 -2580 {lab=IOVSS4}
N 1630 -2600 1680 -2600 {lab=IOVSS4}
N 1680 -2600 1680 -2460 {lab=IOVSS4}
N 1620 -2600 1620 -2580 {lab=VSS4}
N 1570 -2600 1620 -2600 {lab=VSS4}
N 1570 -2600 1570 -2400 {lab=VSS4}
N 1640 -2500 1640 -2480 {lab=IOVDD4}
N 1630 -2500 1630 -2480 {lab=IOVDD4}
N 1630 -2480 1640 -2480 {lab=IOVDD4}
N 1640 -2480 1640 -2440 {lab=IOVDD4}
N 1620 -2500 1620 -2420 {lab=VDD4}
N 1680 -2460 1840 -2460 {lab=IOVSS4}
N 1570 -2400 1730 -2400 {lab=VSS4}
N 1640 -2440 1800 -2440 {lab=IOVDD4}
N 1620 -2420 1780 -2420 {lab=VDD4}
N 1420 -2540 1420 -2340 {lab=ui_p2c[31]}
N 1510 -2680 1510 -2540 {lab=ui_PAD[31]}
N 1470 -2600 1470 -2580 {lab=IOVSS4}
N 1480 -2600 1520 -2600 {lab=IOVSS4}
N 1520 -2600 1520 -2460 {lab=IOVSS4}
N 1460 -2600 1460 -2580 {lab=VSS4}
N 1410 -2600 1460 -2600 {lab=VSS4}
N 1410 -2600 1410 -2400 {lab=VSS4}
N 1470 -2500 1470 -2480 {lab=IOVDD4}
N 1470 -2480 1480 -2480 {lab=IOVDD4}
N 1480 -2480 1480 -2440 {lab=IOVDD4}
N 1460 -2500 1460 -2420 {lab=VDD4}
N 1520 -2460 1680 -2460 {lab=IOVSS4}
N 1410 -2400 1570 -2400 {lab=VSS4}
N 1480 -2440 1640 -2440 {lab=IOVDD4}
N 1460 -2420 1620 -2420 {lab=VDD4}
N 1260 -2540 1260 -2340 {lab=#net16}
N 1350 -2680 1350 -2540 {lab=analog_io[30]}
N 1310 -2600 1310 -2580 {lab=IOVSS4}
N 1310 -2600 1360 -2600 {lab=IOVSS4}
N 1360 -2600 1360 -2460 {lab=IOVSS4}
N 1300 -2600 1300 -2580 {lab=VSS4}
N 1250 -2600 1300 -2600 {lab=VSS4}
N 1250 -2600 1250 -2400 {lab=VSS4}
N 1320 -2500 1320 -2480 {lab=IOVDD4}
N 1310 -2500 1310 -2480 {lab=IOVDD4}
N 1310 -2480 1320 -2480 {lab=IOVDD4}
N 1320 -2480 1320 -2440 {lab=IOVDD4}
N 1300 -2500 1300 -2420 {lab=VDD4}
N 1360 -2460 1520 -2460 {lab=IOVSS4}
N 1250 -2400 1410 -2400 {lab=VSS4}
N 1320 -2440 1480 -2440 {lab=IOVDD4}
N 1300 -2420 1460 -2420 {lab=VDD4}
N 1100 -2540 1100 -2340 {lab=analog_io_padres[29]}
N 1190 -2680 1190 -2540 {lab=analog_io[29]}
N 1150 -2600 1150 -2580 {lab=IOVSS4}
N 1150 -2600 1200 -2600 {lab=IOVSS4}
N 1200 -2600 1200 -2460 {lab=IOVSS4}
N 1140 -2600 1140 -2580 {lab=VSS4}
N 1090 -2600 1140 -2600 {lab=VSS4}
N 1090 -2600 1090 -2400 {lab=VSS4}
N 1160 -2500 1160 -2480 {lab=IOVDD4}
N 1150 -2500 1150 -2480 {lab=IOVDD4}
N 1150 -2480 1160 -2480 {lab=IOVDD4}
N 1140 -2500 1140 -2420 {lab=VDD4}
N 1200 -2460 1360 -2460 {lab=IOVSS4}
N 1090 -2400 1250 -2400 {lab=VSS4}
N 1000 -2440 1160 -2440 {lab=IOVDD4}
N 1140 -2420 1300 -2420 {lab=VDD4}
N 940 -2540 940 -2340 {lab=analog_io_padres[28]}
N 1030 -2680 1030 -2540 {lab=analog_io[28]}
N 990 -2600 990 -2580 {lab=IOVSS4}
N 990 -2600 1040 -2600 {lab=IOVSS4}
N 1040 -2600 1040 -2460 {lab=IOVSS4}
N 980 -2600 980 -2580 {lab=VSS4}
N 930 -2600 980 -2600 {lab=VSS4}
N 930 -2600 930 -2400 {lab=VSS4}
N 1000 -2500 1000 -2480 {lab=IOVDD4}
N 990 -2500 990 -2480 {lab=IOVDD4}
N 990 -2480 1000 -2480 {lab=IOVDD4}
N 1000 -2480 1000 -2440 {lab=IOVDD4}
N 980 -2500 980 -2420 {lab=VDD4}
N 1040 -2460 1200 -2460 {lab=IOVSS4}
N 930 -2400 1090 -2400 {lab=VSS4}
N 980 -2420 1140 -2420 {lab=VDD4}
N 780 -2540 780 -2340 {lab=#net17}
N 870 -2680 870 -2540 {lab=analog_io[27]}
N 830 -2600 830 -2580 {lab=IOVSS4}
N 830 -2600 880 -2600 {lab=IOVSS4}
N 880 -2600 880 -2460 {lab=IOVSS4}
N 820 -2600 820 -2580 {lab=VSS4}
N 770 -2600 820 -2600 {lab=VSS4}
N 770 -2600 770 -2400 {lab=VSS4}
N 840 -2500 840 -2480 {lab=IOVDD4}
N 830 -2500 830 -2480 {lab=IOVDD4}
N 830 -2480 840 -2480 {lab=IOVDD4}
N 840 -2480 840 -2440 {lab=IOVDD4}
N 820 -2500 820 -2420 {lab=VDD4}
N 880 -2460 1040 -2460 {lab=IOVSS4}
N 770 -2400 930 -2400 {lab=VSS4}
N 840 -2440 1000 -2440 {lab=IOVDD4}
N 820 -2420 980 -2420 {lab=VDD4}
N 680 -2620 810 -2620 {lab=SUB}
N 680 -2620 680 -2580 {lab=SUB}
N 560 -2620 560 -2580 {lab=SUB}
N 810 -2620 810 -2580 {lab=SUB}
N 810 -2620 970 -2620 {lab=SUB}
N 970 -2620 970 -2580 {lab=SUB}
N 970 -2620 1130 -2620 {lab=SUB}
N 1130 -2620 1130 -2580 {lab=SUB}
N 1130 -2620 1290 -2620 {lab=SUB}
N 1290 -2620 1290 -2580 {lab=SUB}
N 1290 -2620 1450 -2620 {lab=SUB}
N 1450 -2620 1450 -2580 {lab=SUB}
N 1450 -2620 1610 -2620 {lab=SUB}
N 1610 -2620 1610 -2580 {lab=SUB}
N 1610 -2620 1770 -2620 {lab=SUB}
N 1770 -2620 1770 -2580 {lab=SUB}
N 1770 -2620 1930 -2620 {lab=SUB}
N 1930 -2620 1930 -2580 {lab=SUB}
N 1930 -2620 2090 -2620 {lab=SUB}
N 2090 -2620 2090 -2580 {lab=SUB}
N 2090 -2620 2230 -2620 {lab=SUB}
N 2230 -2620 2230 -2580 {lab=SUB}
N 2230 -2620 2350 -2620 {lab=SUB}
N 2350 -2620 2350 -2580 {lab=SUB}
N 2350 -2620 2640 -2620 {lab=SUB}
N 690 -2500 690 -2420 {lab=VDD4}
N 690 -2420 820 -2420 {lab=VDD4}
N 1160 -2480 1160 -2440 {lab=IOVDD4}
N 1160 -2440 1320 -2440 {lab=IOVDD4}
N 2520 -2400 2620 -2400 {lab=VSS3}
N 2540 -2420 2650 -2420 {lab=VDD3}
N 2560 -2440 2660 -2440 {lab=IOVDD3}
N 2580 -2460 2700 -2460 {lab=IOVSS3}
N 2740 -2620 2800 -2620 {lab=SUB}
N 2740 -2620 2740 -2260 {lab=SUB}
N 2640 -2620 2740 -2620 {lab=SUB}
N 2520 -2400 2520 -2280 {lab=VSS3}
N 2540 -2420 2540 -2250 {lab=VDD3}
N 2560 -2440 2560 -2240 {lab=IOVDD3}
N 2580 -2460 2580 -2220 {lab=IOVSS3}
N 540 -2400 660 -2400 {lab=VSS4}
N 580 -2440 700 -2440 {lab=IOVDD4}
N 610 -2460 720 -2460 {lab=IOVSS4}
N 560 -2620 680 -2620 {lab=SUB}
N 570 -2420 690 -2420 {lab=VDD4}
N 420 -2680 420 -2500 {lab=VSS4}
N 400 -2680 400 -2530 {lab=VDD4}
N 380 -2680 380 -2540 {lab=IOVDD4}
N 360 -2680 360 -2580 {lab=IOVSS4}
N 200 -2520 240 -2520 {lab=SUB}
N 220 -2560 240 -2560 {lab=IOVSS4}
N 220 -2550 240 -2550 {lab=IOVSS4}
N 220 -2560 220 -2550 {lab=IOVSS4}
N 220 -2530 240 -2530 {lab=VSS4}
N 220 -2530 220 -2500 {lab=VSS4}
N 220 -2500 420 -2500 {lab=VSS4}
N 320 -2530 400 -2530 {lab=VDD4}
N 320 -2540 380 -2540 {lab=IOVDD4}
N 220 -2580 220 -2560 {lab=IOVSS4}
N 220 -2580 360 -2580 {lab=IOVSS4}
N 220 -2540 240 -2540 {lab=IOVSS4}
N 220 -2550 220 -2540 {lab=IOVSS4}
N 220 -2240 240 -2240 {lab=VSS1}
N 220 -2240 220 -2210 {lab=VSS1}
N 220 -2210 420 -2210 {lab=VSS1}
N 320 -2240 400 -2240 {lab=VDD1}
N 320 -2250 380 -2250 {lab=IOVDD1}
N 220 -2250 240 -2250 {lab=IOVSS1}
N 220 -2280 220 -2250 {lab=IOVSS1}
N 220 -2280 360 -2280 {lab=IOVSS1}
N 220 -2120 240 -2120 {lab=VSS1}
N 220 -2120 220 -2090 {lab=VSS1}
N 220 -2090 420 -2090 {lab=VSS1}
N 320 -2120 400 -2120 {lab=VDD1}
N 320 -2130 380 -2130 {lab=IOVDD1}
N 220 -2140 240 -2140 {lab=IOVSS1}
N 220 -2130 240 -2130 {lab=IOVSS1}
N 220 -2140 220 -2130 {lab=IOVSS1}
N 220 -2160 220 -2140 {lab=IOVSS1}
N 220 -2160 360 -2160 {lab=IOVSS1}
N 420 -2210 420 -2090 {lab=VSS1}
N 400 -2240 400 -2120 {lab=VDD1}
N 380 -2250 380 -2130 {lab=IOVDD1}
N 360 -2280 360 -2160 {lab=IOVSS1}
N 220 -450 240 -450 {lab=VSS1}
N 220 -450 220 -420 {lab=VSS1}
N 220 -420 420 -420 {lab=VSS1}
N 320 -450 400 -450 {lab=VDD1}
N 320 -460 380 -460 {lab=IOVDD1}
N 220 -470 240 -470 {lab=IOVSS1}
N 220 -460 240 -460 {lab=IOVSS1}
N 220 -470 220 -460 {lab=IOVSS1}
N 220 -490 220 -470 {lab=IOVSS1}
N 220 -490 360 -490 {lab=IOVSS1}
N 220 -570 240 -570 {lab=VSS1}
N 220 -570 220 -540 {lab=VSS1}
N 220 -540 420 -540 {lab=VSS1}
N 320 -580 380 -580 {lab=IOVDD1}
N 220 -580 240 -580 {lab=IOVSS1}
N 420 -650 420 -540 {lab=VSS1}
N 380 -720 380 -580 {lab=IOVDD1}
N 360 -610 360 -490 {lab=IOVSS1}
N 280 -1940 480 -1940 {lab=uo_c2p[8]}
N 140 -2030 280 -2030 {lab=uo_PAD[8]}
N 220 -1990 240 -1990 {lab=IOVSS1}
N 220 -2040 220 -1990 {lab=IOVSS1}
N 220 -2040 360 -2040 {lab=IOVSS1}
N 360 -2160 360 -2040 {lab=IOVSS1}
N 220 -1980 240 -1980 {lab=VSS1}
N 220 -1980 220 -1930 {lab=VSS1}
N 220 -1930 420 -1930 {lab=VSS1}
N 420 -2090 420 -1930 {lab=VSS1}
N 380 -2130 380 -2000 {lab=IOVDD1}
N 320 -1990 340 -1990 {lab=IOVDD1}
N 340 -2000 340 -1990 {lab=IOVDD1}
N 340 -2000 380 -2000 {lab=IOVDD1}
N 400 -2120 400 -1980 {lab=VDD1}
N 280 -1780 480 -1780 {lab=#net18}
N 140 -1870 280 -1870 {lab=analog_io[7]}
N 220 -1830 240 -1830 {lab=IOVSS1}
N 220 -1880 220 -1830 {lab=IOVSS1}
N 220 -1880 360 -1880 {lab=IOVSS1}
N 220 -1820 240 -1820 {lab=VSS1}
N 220 -1820 220 -1770 {lab=VSS1}
N 220 -1770 420 -1770 {lab=VSS1}
N 320 -1840 340 -1840 {lab=IOVDD1}
N 320 -1830 340 -1830 {lab=IOVDD1}
N 340 -1840 340 -1830 {lab=IOVDD1}
N 340 -1840 380 -1840 {lab=IOVDD1}
N 320 -1820 400 -1820 {lab=VDD1}
N 360 -2040 360 -1880 {lab=IOVSS1}
N 420 -1930 420 -1770 {lab=VSS1}
N 380 -2000 380 -1840 {lab=IOVDD1}
N 400 -1980 400 -1820 {lab=VDD1}
N 280 -1620 480 -1620 {lab=analog_io_padres[6]}
N 140 -1710 280 -1710 {lab=analog_io[6]}
N 220 -1670 240 -1670 {lab=IOVSS1}
N 220 -1720 220 -1670 {lab=IOVSS1}
N 220 -1720 360 -1720 {lab=IOVSS1}
N 220 -1660 240 -1660 {lab=VSS1}
N 220 -1660 220 -1610 {lab=VSS1}
N 220 -1610 420 -1610 {lab=VSS1}
N 320 -1680 340 -1680 {lab=IOVDD1}
N 320 -1670 340 -1670 {lab=IOVDD1}
N 340 -1680 340 -1670 {lab=IOVDD1}
N 340 -1680 380 -1680 {lab=IOVDD1}
N 320 -1660 400 -1660 {lab=VDD1}
N 360 -1880 360 -1720 {lab=IOVSS1}
N 420 -1770 420 -1610 {lab=VSS1}
N 380 -1840 380 -1680 {lab=IOVDD1}
N 400 -1820 400 -1660 {lab=VDD1}
N 280 -1460 480 -1460 {lab=analog_io_padres[5]}
N 140 -1550 280 -1550 {lab=analog_io[5]}
N 220 -1510 240 -1510 {lab=IOVSS1}
N 220 -1560 220 -1510 {lab=IOVSS1}
N 220 -1560 360 -1560 {lab=IOVSS1}
N 220 -1500 240 -1500 {lab=VSS1}
N 220 -1500 220 -1450 {lab=VSS1}
N 220 -1450 420 -1450 {lab=VSS1}
N 320 -1520 340 -1520 {lab=IOVDD1}
N 320 -1510 340 -1510 {lab=IOVDD1}
N 340 -1520 340 -1510 {lab=IOVDD1}
N 340 -1520 380 -1520 {lab=IOVDD1}
N 320 -1500 400 -1500 {lab=VDD1}
N 360 -1720 360 -1560 {lab=IOVSS1}
N 420 -1610 420 -1450 {lab=VSS1}
N 380 -1680 380 -1520 {lab=IOVDD1}
N 400 -1660 400 -1500 {lab=VDD1}
N 280 -1300 480 -1300 {lab=#net19}
N 140 -1390 280 -1390 {lab=analog_io[4]}
N 220 -1350 240 -1350 {lab=IOVSS1}
N 220 -1400 220 -1350 {lab=IOVSS1}
N 220 -1400 360 -1400 {lab=IOVSS1}
N 220 -1340 240 -1340 {lab=VSS1}
N 220 -1340 220 -1290 {lab=VSS1}
N 220 -1290 420 -1290 {lab=VSS1}
N 320 -1360 340 -1360 {lab=IOVDD1}
N 320 -1350 340 -1350 {lab=IOVDD1}
N 340 -1360 340 -1350 {lab=IOVDD1}
N 340 -1360 380 -1360 {lab=IOVDD1}
N 320 -1340 400 -1340 {lab=VDD1}
N 360 -1560 360 -1400 {lab=IOVSS1}
N 420 -1450 420 -1290 {lab=VSS1}
N 380 -1520 380 -1360 {lab=IOVDD1}
N 400 -1500 400 -1340 {lab=VDD1}
N 280 -1140 480 -1140 {lab=uo_c2p[3]}
N 140 -1230 280 -1230 {lab=uo_PAD[3]}
N 220 -1240 360 -1240 {lab=IOVSS1}
N 220 -1130 420 -1130 {lab=VSS1}
N 320 -1200 340 -1200 {lab=IOVDD1}
N 340 -1200 340 -1190 {lab=IOVDD1}
N 340 -1200 380 -1200 {lab=IOVDD1}
N 420 -1290 420 -1130 {lab=VSS1}
N 380 -1360 380 -1200 {lab=IOVDD1}
N 400 -1340 400 -1180 {lab=VDD1}
N 280 -980 480 -980 {lab=ui_p2c[2]}
N 140 -1070 280 -1070 {lab=ui_PAD[2]}
N 220 -1030 240 -1030 {lab=IOVSS1}
N 220 -1040 220 -1030 {lab=IOVSS1}
N 220 -1080 360 -1080 {lab=IOVSS1}
N 220 -1020 240 -1020 {lab=VSS1}
N 220 -1020 220 -970 {lab=VSS1}
N 220 -970 420 -970 {lab=VSS1}
N 320 -1030 340 -1030 {lab=IOVDD1}
N 340 -1040 340 -1030 {lab=IOVDD1}
N 320 -1020 400 -1020 {lab=VDD1}
N 420 -1130 420 -970 {lab=VSS1}
N 380 -1040 380 -880 {lab=IOVDD1}
N 400 -1180 400 -1020 {lab=VDD1}
N 280 -820 480 -820 {lab=analog_io_padres[1]}
N 140 -910 280 -910 {lab=analog_io[1]}
N 220 -870 240 -870 {lab=IOVSS1}
N 220 -920 220 -870 {lab=IOVSS1}
N 220 -920 360 -920 {lab=IOVSS1}
N 220 -860 240 -860 {lab=VSS1}
N 220 -860 220 -810 {lab=VSS1}
N 220 -810 420 -810 {lab=VSS1}
N 320 -880 340 -880 {lab=IOVDD1}
N 320 -870 340 -870 {lab=IOVDD1}
N 340 -880 340 -870 {lab=IOVDD1}
N 340 -880 380 -880 {lab=IOVDD1}
N 320 -860 400 -860 {lab=VDD1}
N 360 -1080 360 -920 {lab=IOVSS1}
N 420 -970 420 -810 {lab=VSS1}
N 400 -1020 400 -860 {lab=VDD1}
N 280 -660 480 -660 {lab=analog_io_padres[0]}
N 140 -750 280 -750 {lab=analog_io[0]}
N 220 -710 240 -710 {lab=IOVSS1}
N 220 -760 220 -710 {lab=IOVSS1}
N 220 -760 360 -760 {lab=IOVSS1}
N 220 -700 240 -700 {lab=VSS1}
N 220 -700 220 -650 {lab=VSS1}
N 220 -650 420 -650 {lab=VSS1}
N 320 -720 340 -720 {lab=IOVDD1}
N 320 -710 340 -710 {lab=IOVDD1}
N 340 -720 340 -710 {lab=IOVDD1}
N 340 -720 380 -720 {lab=IOVDD1}
N 320 -700 400 -700 {lab=VDD1}
N 360 -920 360 -760 {lab=IOVSS1}
N 420 -810 420 -650 {lab=VSS1}
N 380 -880 380 -720 {lab=IOVDD1}
N 400 -860 400 -700 {lab=VDD1}
N 200 -690 200 -560 {lab=SUB}
N 200 -560 240 -560 {lab=SUB}
N 200 -440 240 -440 {lab=SUB}
N 200 -690 240 -690 {lab=SUB}
N 200 -850 200 -690 {lab=SUB}
N 200 -850 240 -850 {lab=SUB}
N 200 -1010 200 -850 {lab=SUB}
N 200 -1010 240 -1010 {lab=SUB}
N 200 -1170 240 -1170 {lab=SUB}
N 200 -1170 200 -1010 {lab=SUB}
N 200 -1330 240 -1330 {lab=SUB}
N 200 -1490 200 -1330 {lab=SUB}
N 200 -1490 240 -1490 {lab=SUB}
N 200 -1650 200 -1490 {lab=SUB}
N 200 -1650 240 -1650 {lab=SUB}
N 200 -1810 200 -1650 {lab=SUB}
N 200 -1810 240 -1810 {lab=SUB}
N 200 -1970 240 -1970 {lab=SUB}
N 200 -1970 200 -1810 {lab=SUB}
N 200 -2110 240 -2110 {lab=SUB}
N 200 -2230 200 -2110 {lab=SUB}
N 200 -2230 240 -2230 {lab=SUB}
N 200 -2520 200 -2230 {lab=SUB}
N 320 -570 400 -570 {lab=VDD1}
N 400 -700 400 -570 {lab=VDD1}
N 340 -1040 380 -1040 {lab=IOVDD1}
N 380 -1200 380 -1040 {lab=IOVDD1}
N 200 -2620 200 -2520 {lab=SUB}
N 420 -540 420 -420 {lab=VSS1}
N 380 -580 380 -460 {lab=IOVDD1}
N 200 -560 200 -440 {lab=SUB}
N 400 -570 400 -450 {lab=VDD1}
N 200 -2620 560 -2620 {lab=SUB}
N 200 -2680 200 -2620 {lab=SUB}
N 420 -2400 540 -2400 {lab=VSS4}
N 420 -2500 420 -2400 {lab=VSS4}
N 400 -2420 570 -2420 {lab=VDD4}
N 400 -2530 400 -2420 {lab=VDD4}
N 380 -2440 580 -2440 {lab=IOVDD4}
N 380 -2540 380 -2440 {lab=IOVDD4}
N 360 -2460 610 -2460 {lab=IOVSS4}
N 360 -2580 360 -2460 {lab=IOVSS4}
N 220 -590 220 -580 {lab=IOVSS1}
N 220 -610 360 -610 {lab=IOVSS1}
N 360 -760 360 -610 {lab=IOVSS1}
N 220 -590 240 -590 {lab=IOVSS1}
N 220 -610 220 -590 {lab=IOVSS1}
N 200 -440 200 -80 {lab=SUB}
N 60 -80 200 -80 {lab=SUB}
N 360 -490 360 -240 {lab=IOVSS1}
N 240 -240 360 -240 {lab=IOVSS1}
N 380 -460 380 -260 {lab=IOVDD1}
N 280 -260 380 -260 {lab=IOVDD1}
N 400 -450 400 -280 {lab=VDD1}
N 290 -280 400 -280 {lab=VDD1}
N 420 -420 420 -300 {lab=VSS1}
N 320 -300 420 -300 {lab=VSS1}
N 1060 260 1260 260 {lab=IOVSS1}
N 1260 260 1260 320 {lab=IOVSS1}
N 1260 380 1260 420 {lab=SUB}
N 1120 420 1260 420 {lab=SUB}
N 1260 420 1360 420 {lab=SUB}
N 1360 380 1360 420 {lab=SUB}
N 1140 200 1360 200 {lab=VSS1}
N 1360 200 1360 320 {lab=VSS1}
N 710 -2600 710 -2580 {lab=IOVSS4}
N 700 -2600 710 -2600 {lab=IOVSS4}
N 710 -80 840 -80 {lab=SUB}
N 870 -300 870 -100 {lab=VSS2}
N 730 -300 870 -300 {lab=VSS2}
N 810 -120 810 -100 {lab=IOVSS2}
N 810 -100 820 -100 {lab=IOVSS2}
N 820 -120 820 -100 {lab=IOVSS2}
N 780 -100 810 -100 {lab=IOVSS2}
N 780 -240 780 -100 {lab=IOVSS2}
N 660 -240 780 -240 {lab=IOVSS2}
N 830 -280 830 -200 {lab=VDD2}
N 700 -280 830 -280 {lab=VDD2}
N 200 -1330 200 -1170 {lab=SUB}
N 220 -1040 240 -1040 {lab=IOVSS1}
N 220 -1080 220 -1040 {lab=IOVSS1}
N 200 -2110 200 -1970 {lab=SUB}
N 320 -1980 400 -1980 {lab=VDD1}
N 320 -1180 400 -1180 {lab=VDD1}
N 1480 -2600 1480 -2580 {lab=IOVSS4}
N 1470 -2600 1480 -2600 {lab=IOVSS4}
N 360 -1240 360 -1080 {lab=IOVSS1}
N 220 -1190 240 -1190 {lab=IOVSS1}
N 220 -1240 220 -1190 {lab=IOVSS1}
N 220 -1180 220 -1130 {lab=VSS1}
N 220 -1180 240 -1180 {lab=VSS1}
N 360 -1400 360 -1240 {lab=IOVSS1}
N 320 -1190 340 -1190 {lab=IOVDD1}
N 320 -2000 340 -2000 {lab=IOVDD1}
N 160 520 440 520 {lab=VSS2}
N 160 540 410 540 {lab=VDD2}
N 160 560 400 560 {lab=IOVDD2}
N 160 580 360 580 {lab=IOVSS2}
N 160 740 420 740 {lab=SUB}
N 420 700 420 740 {lab=SUB}
N 380 700 380 720 {lab=IOVSS2}
N 390 700 390 720 {lab=IOVSS2}
N 380 720 390 720 {lab=IOVSS2}
N 410 700 410 720 {lab=VSS2}
N 410 720 440 720 {lab=VSS2}
N 440 520 440 720 {lab=VSS2}
N 410 540 410 620 {lab=VDD2}
N 400 560 400 620 {lab=IOVDD2}
N 360 720 380 720 {lab=IOVSS2}
N 360 580 360 720 {lab=IOVSS2}
N 400 700 400 720 {lab=IOVSS2}
N 390 720 400 720 {lab=IOVSS2}
N 500 700 500 720 {lab=IOVSS2}
N 510 700 510 720 {lab=IOVSS2}
N 500 720 510 720 {lab=IOVSS2}
N 530 700 530 720 {lab=VSS2}
N 530 720 560 720 {lab=VSS2}
N 560 520 560 720 {lab=VSS2}
N 530 540 530 620 {lab=VDD2}
N 520 560 520 620 {lab=IOVDD2}
N 480 720 500 720 {lab=IOVSS2}
N 480 580 480 720 {lab=IOVSS2}
N 520 700 520 720 {lab=IOVSS2}
N 510 720 520 720 {lab=IOVSS2}
N 440 520 560 520 {lab=VSS2}
N 410 540 530 540 {lab=VDD2}
N 400 560 520 560 {lab=IOVDD2}
N 360 580 480 580 {lab=IOVSS2}
N 620 700 620 720 {lab=IOVSS2}
N 630 700 630 720 {lab=IOVSS2}
N 620 720 630 720 {lab=IOVSS2}
N 650 700 650 720 {lab=VSS2}
N 650 720 680 720 {lab=VSS2}
N 680 520 680 720 {lab=VSS2}
N 650 540 650 620 {lab=VDD2}
N 640 560 640 620 {lab=IOVDD2}
N 600 720 620 720 {lab=IOVSS2}
N 600 580 600 720 {lab=IOVSS2}
N 640 700 640 720 {lab=IOVSS2}
N 630 720 640 720 {lab=IOVSS2}
N 560 520 680 520 {lab=VSS2}
N 530 540 650 540 {lab=VDD2}
N 520 560 640 560 {lab=IOVDD2}
N 480 580 600 580 {lab=IOVSS2}
N 740 700 740 720 {lab=IOVSS2}
N 750 700 750 720 {lab=IOVSS2}
N 740 720 750 720 {lab=IOVSS2}
N 770 700 770 720 {lab=VSS2}
N 770 720 800 720 {lab=VSS2}
N 800 520 800 720 {lab=VSS2}
N 770 540 770 620 {lab=VDD2}
N 760 560 760 620 {lab=IOVDD2}
N 720 720 740 720 {lab=IOVSS2}
N 720 580 720 720 {lab=IOVSS2}
N 760 700 760 720 {lab=IOVSS2}
N 750 720 760 720 {lab=IOVSS2}
N 680 520 800 520 {lab=VSS2}
N 650 540 770 540 {lab=VDD2}
N 640 560 760 560 {lab=IOVDD2}
N 600 580 720 580 {lab=IOVSS2}
N 960 700 960 720 {lab=IOVSS2}
N 970 700 970 720 {lab=IOVSS2}
N 960 720 970 720 {lab=IOVSS2}
N 990 700 990 720 {lab=VSS2}
N 990 720 1020 720 {lab=VSS2}
N 1020 520 1020 720 {lab=VSS2}
N 990 540 990 620 {lab=VDD2}
N 980 560 980 620 {lab=IOVDD2}
N 940 720 960 720 {lab=IOVSS2}
N 940 580 940 720 {lab=IOVSS2}
N 980 700 980 720 {lab=IOVSS2}
N 970 720 980 720 {lab=IOVSS2}
N 800 520 1020 520 {lab=VSS2}
N 770 540 990 540 {lab=VDD2}
N 760 560 980 560 {lab=IOVDD2}
N 720 580 940 580 {lab=IOVSS2}
N 1080 700 1080 720 {lab=IOVSS2}
N 1090 700 1090 720 {lab=IOVSS2}
N 1080 720 1090 720 {lab=IOVSS2}
N 1110 700 1110 720 {lab=VSS2}
N 1110 720 1140 720 {lab=VSS2}
N 1140 520 1140 720 {lab=VSS2}
N 1110 540 1110 620 {lab=VDD2}
N 1100 560 1100 620 {lab=IOVDD2}
N 1060 720 1080 720 {lab=IOVSS2}
N 1060 580 1060 720 {lab=IOVSS2}
N 1100 700 1100 720 {lab=IOVSS2}
N 1090 720 1100 720 {lab=IOVSS2}
N 1020 520 1140 520 {lab=VSS2}
N 990 540 1110 540 {lab=VDD2}
N 980 560 1100 560 {lab=IOVDD2}
N 940 580 1060 580 {lab=IOVSS2}
N 1000 740 1120 740 {lab=SUB}
N 1120 700 1120 740 {lab=SUB}
N 1000 700 1000 740 {lab=SUB}
N 780 740 1000 740 {lab=SUB}
N 780 700 780 740 {lab=SUB}
N 660 740 780 740 {lab=SUB}
N 660 700 660 740 {lab=SUB}
N 540 740 660 740 {lab=SUB}
N 540 700 540 740 {lab=SUB}
N 420 740 540 740 {lab=SUB}
N 1060 580 1260 580 {lab=IOVSS2}
N 1260 580 1260 640 {lab=IOVSS2}
N 1260 700 1260 740 {lab=SUB}
N 1120 740 1260 740 {lab=SUB}
N 1260 740 1360 740 {lab=SUB}
N 1360 700 1360 740 {lab=SUB}
N 1140 520 1360 520 {lab=VSS2}
N 1360 520 1360 640 {lab=VSS2}
N 160 840 440 840 {lab=VSS3}
N 160 860 410 860 {lab=VDD3}
N 160 880 400 880 {lab=IOVDD3}
N 160 900 360 900 {lab=IOVSS3}
N 160 1060 420 1060 {lab=SUB}
N 420 1020 420 1060 {lab=SUB}
N 380 1020 380 1040 {lab=IOVSS3}
N 390 1020 390 1040 {lab=IOVSS3}
N 380 1040 390 1040 {lab=IOVSS3}
N 410 1020 410 1040 {lab=VSS3}
N 410 1040 440 1040 {lab=VSS3}
N 440 840 440 1040 {lab=VSS3}
N 410 860 410 940 {lab=VDD3}
N 400 880 400 940 {lab=IOVDD3}
N 360 1040 380 1040 {lab=IOVSS3}
N 360 900 360 1040 {lab=IOVSS3}
N 400 1020 400 1040 {lab=IOVSS3}
N 390 1040 400 1040 {lab=IOVSS3}
N 500 1020 500 1040 {lab=IOVSS3}
N 510 1020 510 1040 {lab=IOVSS3}
N 500 1040 510 1040 {lab=IOVSS3}
N 530 1020 530 1040 {lab=VSS3}
N 530 1040 560 1040 {lab=VSS3}
N 560 840 560 1040 {lab=VSS3}
N 530 860 530 940 {lab=VDD3}
N 520 880 520 940 {lab=IOVDD3}
N 480 1040 500 1040 {lab=IOVSS3}
N 480 900 480 1040 {lab=IOVSS3}
N 520 1020 520 1040 {lab=IOVSS3}
N 510 1040 520 1040 {lab=IOVSS3}
N 440 840 560 840 {lab=VSS3}
N 410 860 530 860 {lab=VDD3}
N 400 880 520 880 {lab=IOVDD3}
N 360 900 480 900 {lab=IOVSS3}
N 620 1020 620 1040 {lab=IOVSS3}
N 630 1020 630 1040 {lab=IOVSS3}
N 620 1040 630 1040 {lab=IOVSS3}
N 650 1020 650 1040 {lab=VSS3}
N 650 1040 680 1040 {lab=VSS3}
N 680 840 680 1040 {lab=VSS3}
N 650 860 650 940 {lab=VDD3}
N 640 880 640 940 {lab=IOVDD3}
N 600 1040 620 1040 {lab=IOVSS3}
N 600 900 600 1040 {lab=IOVSS3}
N 640 1020 640 1040 {lab=IOVSS3}
N 630 1040 640 1040 {lab=IOVSS3}
N 560 840 680 840 {lab=VSS3}
N 530 860 650 860 {lab=VDD3}
N 520 880 640 880 {lab=IOVDD3}
N 480 900 600 900 {lab=IOVSS3}
N 740 1020 740 1040 {lab=IOVSS3}
N 750 1020 750 1040 {lab=IOVSS3}
N 740 1040 750 1040 {lab=IOVSS3}
N 770 1020 770 1040 {lab=VSS3}
N 770 1040 800 1040 {lab=VSS3}
N 800 840 800 1040 {lab=VSS3}
N 770 860 770 940 {lab=VDD3}
N 760 880 760 940 {lab=IOVDD3}
N 720 1040 740 1040 {lab=IOVSS3}
N 720 900 720 1040 {lab=IOVSS3}
N 760 1020 760 1040 {lab=IOVSS3}
N 750 1040 760 1040 {lab=IOVSS3}
N 680 840 800 840 {lab=VSS3}
N 650 860 770 860 {lab=VDD3}
N 640 880 760 880 {lab=IOVDD3}
N 600 900 720 900 {lab=IOVSS3}
N 960 1020 960 1040 {lab=IOVSS3}
N 970 1020 970 1040 {lab=IOVSS3}
N 960 1040 970 1040 {lab=IOVSS3}
N 990 1020 990 1040 {lab=VSS3}
N 990 1040 1020 1040 {lab=VSS3}
N 1020 840 1020 1040 {lab=VSS3}
N 990 860 990 940 {lab=VDD3}
N 980 880 980 940 {lab=IOVDD3}
N 940 1040 960 1040 {lab=IOVSS3}
N 940 900 940 1040 {lab=IOVSS3}
N 980 1020 980 1040 {lab=IOVSS3}
N 970 1040 980 1040 {lab=IOVSS3}
N 800 840 1020 840 {lab=VSS3}
N 770 860 990 860 {lab=VDD3}
N 760 880 980 880 {lab=IOVDD3}
N 720 900 940 900 {lab=IOVSS3}
N 1080 1020 1080 1040 {lab=IOVSS3}
N 1090 1020 1090 1040 {lab=IOVSS3}
N 1080 1040 1090 1040 {lab=IOVSS3}
N 1110 1020 1110 1040 {lab=VSS3}
N 1110 1040 1140 1040 {lab=VSS3}
N 1140 840 1140 1040 {lab=VSS3}
N 1110 860 1110 940 {lab=VDD3}
N 1100 880 1100 940 {lab=IOVDD3}
N 1060 1040 1080 1040 {lab=IOVSS3}
N 1060 900 1060 1040 {lab=IOVSS3}
N 1100 1020 1100 1040 {lab=IOVSS3}
N 1090 1040 1100 1040 {lab=IOVSS3}
N 1020 840 1140 840 {lab=VSS3}
N 990 860 1110 860 {lab=VDD3}
N 980 880 1100 880 {lab=IOVDD3}
N 940 900 1060 900 {lab=IOVSS3}
N 1000 1060 1120 1060 {lab=SUB}
N 1120 1020 1120 1060 {lab=SUB}
N 1000 1020 1000 1060 {lab=SUB}
N 780 1060 1000 1060 {lab=SUB}
N 780 1020 780 1060 {lab=SUB}
N 660 1060 780 1060 {lab=SUB}
N 660 1020 660 1060 {lab=SUB}
N 540 1060 660 1060 {lab=SUB}
N 540 1020 540 1060 {lab=SUB}
N 420 1060 540 1060 {lab=SUB}
N 1060 900 1260 900 {lab=IOVSS3}
N 1260 900 1260 960 {lab=IOVSS3}
N 1260 1020 1260 1060 {lab=SUB}
N 1120 1060 1260 1060 {lab=SUB}
N 1260 1060 1360 1060 {lab=SUB}
N 1360 1020 1360 1060 {lab=SUB}
N 1140 840 1360 840 {lab=VSS3}
N 1360 840 1360 960 {lab=VSS3}
N 160 1160 440 1160 {lab=VSS4}
N 160 1180 410 1180 {lab=VDD4}
N 160 1200 400 1200 {lab=IOVDD4}
N 160 1220 360 1220 {lab=IOVSS4}
N 160 1380 420 1380 {lab=SUB}
N 420 1340 420 1380 {lab=SUB}
N 380 1340 380 1360 {lab=IOVSS4}
N 390 1340 390 1360 {lab=IOVSS4}
N 380 1360 390 1360 {lab=IOVSS4}
N 410 1340 410 1360 {lab=VSS4}
N 410 1360 440 1360 {lab=VSS4}
N 440 1160 440 1360 {lab=VSS4}
N 410 1180 410 1260 {lab=VDD4}
N 400 1200 400 1260 {lab=IOVDD4}
N 360 1360 380 1360 {lab=IOVSS4}
N 360 1220 360 1360 {lab=IOVSS4}
N 400 1340 400 1360 {lab=IOVSS4}
N 390 1360 400 1360 {lab=IOVSS4}
N 500 1340 500 1360 {lab=IOVSS4}
N 510 1340 510 1360 {lab=IOVSS4}
N 500 1360 510 1360 {lab=IOVSS4}
N 530 1340 530 1360 {lab=VSS4}
N 530 1360 560 1360 {lab=VSS4}
N 560 1160 560 1360 {lab=VSS4}
N 530 1180 530 1260 {lab=VDD4}
N 520 1200 520 1260 {lab=IOVDD4}
N 480 1360 500 1360 {lab=IOVSS4}
N 480 1220 480 1360 {lab=IOVSS4}
N 520 1340 520 1360 {lab=IOVSS4}
N 510 1360 520 1360 {lab=IOVSS4}
N 440 1160 560 1160 {lab=VSS4}
N 410 1180 530 1180 {lab=VDD4}
N 400 1200 520 1200 {lab=IOVDD4}
N 360 1220 480 1220 {lab=IOVSS4}
N 620 1340 620 1360 {lab=IOVSS4}
N 630 1340 630 1360 {lab=IOVSS4}
N 620 1360 630 1360 {lab=IOVSS4}
N 650 1340 650 1360 {lab=VSS4}
N 650 1360 680 1360 {lab=VSS4}
N 680 1160 680 1360 {lab=VSS4}
N 650 1180 650 1260 {lab=VDD4}
N 640 1200 640 1260 {lab=IOVDD4}
N 600 1360 620 1360 {lab=IOVSS4}
N 600 1220 600 1360 {lab=IOVSS4}
N 640 1340 640 1360 {lab=IOVSS4}
N 630 1360 640 1360 {lab=IOVSS4}
N 560 1160 680 1160 {lab=VSS4}
N 530 1180 650 1180 {lab=VDD4}
N 520 1200 640 1200 {lab=IOVDD4}
N 480 1220 600 1220 {lab=IOVSS4}
N 740 1340 740 1360 {lab=IOVSS4}
N 750 1340 750 1360 {lab=IOVSS4}
N 740 1360 750 1360 {lab=IOVSS4}
N 770 1340 770 1360 {lab=VSS4}
N 770 1360 800 1360 {lab=VSS4}
N 800 1160 800 1360 {lab=VSS4}
N 770 1180 770 1260 {lab=VDD4}
N 760 1200 760 1260 {lab=IOVDD4}
N 720 1360 740 1360 {lab=IOVSS4}
N 720 1220 720 1360 {lab=IOVSS4}
N 760 1340 760 1360 {lab=IOVSS4}
N 750 1360 760 1360 {lab=IOVSS4}
N 680 1160 800 1160 {lab=VSS4}
N 650 1180 770 1180 {lab=VDD4}
N 640 1200 760 1200 {lab=IOVDD4}
N 600 1220 720 1220 {lab=IOVSS4}
N 960 1340 960 1360 {lab=IOVSS4}
N 970 1340 970 1360 {lab=IOVSS4}
N 960 1360 970 1360 {lab=IOVSS4}
N 990 1340 990 1360 {lab=VSS4}
N 990 1360 1020 1360 {lab=VSS4}
N 1020 1160 1020 1360 {lab=VSS4}
N 990 1180 990 1260 {lab=VDD4}
N 980 1200 980 1260 {lab=IOVDD4}
N 940 1360 960 1360 {lab=IOVSS4}
N 940 1220 940 1360 {lab=IOVSS4}
N 980 1340 980 1360 {lab=IOVSS4}
N 970 1360 980 1360 {lab=IOVSS4}
N 800 1160 1020 1160 {lab=VSS4}
N 770 1180 990 1180 {lab=VDD4}
N 760 1200 980 1200 {lab=IOVDD4}
N 720 1220 940 1220 {lab=IOVSS4}
N 1080 1340 1080 1360 {lab=IOVSS4}
N 1090 1340 1090 1360 {lab=IOVSS4}
N 1080 1360 1090 1360 {lab=IOVSS4}
N 1110 1340 1110 1360 {lab=VSS4}
N 1110 1360 1140 1360 {lab=VSS4}
N 1140 1160 1140 1360 {lab=VSS4}
N 1110 1180 1110 1260 {lab=VDD4}
N 1100 1200 1100 1260 {lab=IOVDD4}
N 1060 1360 1080 1360 {lab=IOVSS4}
N 1060 1220 1060 1360 {lab=IOVSS4}
N 1100 1340 1100 1360 {lab=IOVSS4}
N 1090 1360 1100 1360 {lab=IOVSS4}
N 1020 1160 1140 1160 {lab=VSS4}
N 990 1180 1110 1180 {lab=VDD4}
N 980 1200 1100 1200 {lab=IOVDD4}
N 940 1220 1060 1220 {lab=IOVSS4}
N 1000 1380 1120 1380 {lab=SUB}
N 1120 1340 1120 1380 {lab=SUB}
N 1000 1340 1000 1380 {lab=SUB}
N 780 1380 1000 1380 {lab=SUB}
N 780 1340 780 1380 {lab=SUB}
N 660 1380 780 1380 {lab=SUB}
N 660 1340 660 1380 {lab=SUB}
N 540 1380 660 1380 {lab=SUB}
N 540 1340 540 1380 {lab=SUB}
N 420 1380 540 1380 {lab=SUB}
N 1060 1220 1260 1220 {lab=IOVSS4}
N 1260 1220 1260 1280 {lab=IOVSS4}
N 1260 1340 1260 1380 {lab=SUB}
N 1120 1380 1260 1380 {lab=SUB}
N 1260 1380 1360 1380 {lab=SUB}
N 1360 1340 1360 1380 {lab=SUB}
N 1140 1160 1360 1160 {lab=VSS4}
N 1360 1160 1360 1280 {lab=VSS4}
C {sg13g2_Corner_noptap.sym} 290 -160 0 0 {name=x5}
C {sg13g2_IOPadIn.sym} 580 -160 0 0 {name=x6}
C {sg13g2_IOPadVss.sym} 700 -160 0 0 {name=x10}
C {sg13g2_Filler4000.sym} 400 340 0 0 {name=x11[1:0]}
C {sg13g2_Filler1000.sym} 520 340 0 0 {name=x12[1:0]}
C {sg13g2_Filler400.sym} 640 340 0 0 {name=x13[1:0]}
C {sg13g2_Filler200.sym} 760 340 0 0 {name=x14[1:0]}
C {sg13g2_IOPadVdd.sym} 830 -160 0 0 {name=x15}
C {sg13g2_Filler4000.sym} 980 340 0 0 {name=x16[11:0]}
C {sg13g2_Filler400.sym} 1100 340 0 0 {name=x17[11:0]}
C {sg13g2_IOPadAnalog.sym} 1000 -160 0 0 {name=x1}
C {sg13g2_IOPadAnalog.sym} 1160 -160 0 0 {name=x2}
C {sg13g2_IOPadAnalog.sym} 1320 -160 0 0 {name=x3}
C {sg13g2_IOPadAnalog.sym} 1480 -160 0 0 {name=x4}
C {sg13g2_IOPadAnalog.sym} 1640 -160 0 0 {name=x11}
C {sg13g2_IOPadAnalog.sym} 1800 -160 0 0 {name=x12}
C {sg13g2_IOPadAnalog.sym} 1960 -160 0 0 {name=x13}
C {sg13g2_IOPadAnalog.sym} 2120 -160 0 0 {name=x14}
C {sg13g2_IOPadIOVdd.sym} 2260 -160 0 0 {name=x16}
C {sg13g2_IOPadIOVss.sym} 2370 -160 0 0 {name=x17}
C {iopin.sym} 60 -300 0 1 {name=p1 lab=VSS1}
C {iopin.sym} 60 -280 0 1 {name=p2 lab=VDD1}
C {iopin.sym} 60 -260 0 1 {name=p3 lab=IOVDD1}
C {iopin.sym} 60 -240 0 1 {name=p4 lab=IOVSS1}
C {lab_pin.sym} 160 200 0 0 {name=p6 sig_type=std_logic lab=VSS1}
C {lab_pin.sym} 160 220 0 0 {name=p7 sig_type=std_logic lab=VDD1}
C {lab_pin.sym} 160 240 0 0 {name=p8 sig_type=std_logic lab=IOVDD1}
C {lab_pin.sym} 160 260 0 0 {name=p9 sig_type=std_logic lab=IOVSS1}
C {lab_pin.sym} 160 420 0 0 {name=p10 sig_type=std_logic lab=SUB}
C {iopin.sym} 70 10 2 0 {name=p11 lab=analog_io[35:32]}
C {lab_pin.sym} 2070 -20 3 0 {name=p12 sig_type=std_logic lab=analog_io[17]}
C {lab_pin.sym} 1910 -20 3 0 {name=p13 sig_type=std_logic lab=analog_io[16]}
C {lab_pin.sym} 1750 -20 3 0 {name=p14 sig_type=std_logic lab=analog_io[15]}
C {lab_pin.sym} 1590 -20 3 0 {name=p15 sig_type=std_logic lab=analog_io[14]}
C {lab_pin.sym} 1430 -20 3 0 {name=p16 sig_type=std_logic lab=analog_io[13]}
C {lab_pin.sym} 1270 -20 3 0 {name=p17 sig_type=std_logic lab=analog_io[12]}
C {lab_pin.sym} 1110 -20 3 0 {name=p18 sig_type=std_logic lab=analog_io[11]}
C {lab_pin.sym} 950 -20 3 0 {name=p19 sig_type=std_logic lab=analog_io[10]}
C {lab_pin.sym} 530 -20 3 0 {name=p20 sig_type=std_logic lab=ui_PAD[9]}
C {sg13g2_Corner_noptap.sym} 2660 -170 3 0 {name=x7}
C {sg13g2_IOPadAnalog.sym} 2660 -720 3 0 {name=x8}
C {sg13g2_IOPadVss.sym} 2660 -580 3 0 {name=x9}
C {sg13g2_IOPadVdd.sym} 2660 -460 3 0 {name=x18}
C {sg13g2_IOPadAnalog.sym} 2660 -880 3 0 {name=x19}
C {sg13g2_IOPadAnalog.sym} 2660 -1040 3 0 {name=x20}
C {sg13g2_IOPadAnalog.sym} 2660 -1200 3 0 {name=x21}
C {sg13g2_IOPadAnalog.sym} 2660 -1360 3 0 {name=x22}
C {sg13g2_IOPadAnalog.sym} 2660 -1520 3 0 {name=x23}
C {sg13g2_IOPadAnalog.sym} 2660 -1680 3 0 {name=x24}
C {sg13g2_IOPadAnalog.sym} 2660 -1840 3 0 {name=x25}
C {sg13g2_IOPadAnalog.sym} 2660 -2000 3 0 {name=x26}
C {sg13g2_IOPadIOVdd.sym} 2660 -2140 3 0 {name=x27}
C {sg13g2_IOPadIOVss.sym} 2660 -2250 3 0 {name=x28}
C {lab_pin.sym} 2800 -1950 2 0 {name=p26 sig_type=std_logic lab=analog_io[26]}
C {lab_pin.sym} 2800 -1790 2 0 {name=p27 sig_type=std_logic lab=analog_io[25]}
C {lab_pin.sym} 2800 -1630 2 0 {name=p28 sig_type=std_logic lab=analog_io[24]}
C {lab_pin.sym} 2800 -1470 2 0 {name=p29 sig_type=std_logic lab=analog_io[23]}
C {lab_pin.sym} 2800 -1310 2 0 {name=p30 sig_type=std_logic lab=analog_io[22]}
C {lab_pin.sym} 2800 -1150 2 0 {name=p31 sig_type=std_logic lab=analog_io[21]}
C {lab_pin.sym} 2800 -990 2 0 {name=p32 sig_type=std_logic lab=analog_io[20]}
C {lab_pin.sym} 2800 -830 2 0 {name=p33 sig_type=std_logic lab=analog_io[19]}
C {lab_pin.sym} 2800 -670 2 0 {name=p34 sig_type=std_logic lab=analog_io[18]}
C {noconn.sym} 2460 -760 3 0 {name=l10}
C {noconn.sym} 2460 -1080 3 0 {name=l12}
C {noconn.sym} 2460 -1240 3 0 {name=l13}
C {noconn.sym} 2460 -1560 3 0 {name=l15}
C {noconn.sym} 2460 -1720 3 0 {name=l16}
C {noconn.sym} 2460 -2040 3 0 {name=l18}
C {noconn.sym} 2740 -20 3 0 {name=l23}
C {lab_pin.sym} 60 -80 0 0 {name=p5 sig_type=std_logic lab=SUB}
C {sg13g2_Corner_noptap.sym} 2650 -2540 2 0 {name=x29}
C {sg13g2_IOPadAnalog.sym} 2100 -2540 2 0 {name=x30}
C {sg13g2_IOPadIOVdd.sym} 2240 -2540 2 0 {name=x31}
C {sg13g2_IOPadIOVss.sym} 2360 -2540 2 0 {name=x32}
C {sg13g2_IOPadAnalog.sym} 1940 -2540 2 0 {name=x33}
C {sg13g2_IOPadAnalog.sym} 1780 -2540 2 0 {name=x34}
C {sg13g2_IOPadAnalog.sym} 1620 -2540 2 0 {name=x35}
C {sg13g2_IOPadIn.sym} 1460 -2540 2 0 {name=x36}
C {sg13g2_IOPadAnalog.sym} 1300 -2540 2 0 {name=x37}
C {sg13g2_IOPadAnalog.sym} 1140 -2540 2 0 {name=x38}
C {sg13g2_IOPadAnalog.sym} 980 -2540 2 0 {name=x39}
C {sg13g2_IOPadAnalog.sym} 820 -2540 2 0 {name=x40}
C {sg13g2_IOPadVdd.sym} 570 -2540 2 0 {name=x41}
C {sg13g2_IOPadVss.sym} 690 -2540 2 0 {name=x42}
C {lab_pin.sym} 870 -2680 1 0 {name=p21 sig_type=std_logic lab=analog_io[27]}
C {lab_pin.sym} 1030 -2680 1 0 {name=p22 sig_type=std_logic lab=analog_io[28]}
C {lab_pin.sym} 1190 -2680 1 0 {name=p23 sig_type=std_logic lab=analog_io[29]}
C {lab_pin.sym} 1350 -2680 1 0 {name=p24 sig_type=std_logic lab=analog_io[30]}
C {lab_pin.sym} 1510 -2680 1 0 {name=p25 sig_type=std_logic lab=ui_PAD[31]}
C {lab_pin.sym} 1670 -2680 1 0 {name=p35 sig_type=std_logic lab=analog_io[32]}
C {lab_pin.sym} 1830 -2680 1 0 {name=p36 sig_type=std_logic lab=analog_io[33]}
C {lab_pin.sym} 1990 -2680 1 0 {name=p37 sig_type=std_logic lab=analog_io[34]}
C {lab_pin.sym} 2150 -2680 1 0 {name=p38 sig_type=std_logic lab=analog_io[35]}
C {noconn.sym} 2060 -2340 2 0 {name=l24}
C {noconn.sym} 1580 -2340 2 0 {name=l27}
C {noconn.sym} 1260 -2340 2 0 {name=l29}
C {noconn.sym} 780 -2340 2 0 {name=l32}
C {noconn.sym} 2800 -2620 2 0 {name=l37}
C {sg13g2_Corner_noptap.sym} 280 -2530 1 0 {name=x43}
C {sg13g2_IOPadOut4mA.sym} 280 -1990 1 1 {name=x44}
C {sg13g2_IOPadIOVdd.sym} 280 -2120 1 0 {name=x45}
C {sg13g2_IOPadIOVss.sym} 280 -2240 1 0 {name=x46}
C {sg13g2_IOPadAnalog.sym} 280 -1820 1 0 {name=x47}
C {sg13g2_IOPadAnalog.sym} 280 -1660 1 0 {name=x48}
C {sg13g2_IOPadAnalog.sym} 280 -1500 1 0 {name=x49}
C {sg13g2_IOPadAnalog.sym} 280 -1340 1 0 {name=x50}
C {sg13g2_IOPadOut4mA.sym} 280 -1190 1 1 {name=x51}
C {sg13g2_IOPadIn.sym} 280 -1020 1 0 {name=x52}
C {sg13g2_IOPadAnalog.sym} 280 -860 1 0 {name=x53}
C {sg13g2_IOPadAnalog.sym} 280 -700 1 0 {name=x54}
C {sg13g2_IOPadVdd.sym} 280 -450 1 0 {name=x55}
C {sg13g2_IOPadVss.sym} 280 -570 1 0 {name=x56}
C {lab_pin.sym} 140 -750 0 0 {name=p39 sig_type=std_logic lab=analog_io[0]}
C {lab_pin.sym} 140 -910 0 0 {name=p40 sig_type=std_logic lab=analog_io[1]}
C {lab_pin.sym} 140 -1070 0 0 {name=p41 sig_type=std_logic lab=ui_PAD[2]}
C {lab_pin.sym} 140 -1230 0 0 {name=p42 sig_type=std_logic lab=uo_PAD[3]}
C {lab_pin.sym} 140 -1390 0 0 {name=p43 sig_type=std_logic lab=analog_io[4]}
C {lab_pin.sym} 140 -1550 0 0 {name=p44 sig_type=std_logic lab=analog_io[5]}
C {lab_pin.sym} 140 -1710 0 0 {name=p45 sig_type=std_logic lab=analog_io[6]}
C {lab_pin.sym} 140 -1870 0 0 {name=p46 sig_type=std_logic lab=analog_io[7]}
C {lab_pin.sym} 140 -2030 0 0 {name=p47 sig_type=std_logic lab=uo_PAD[8]}
C {noconn.sym} 480 -1780 1 0 {name=l39}
C {noconn.sym} 480 -1300 1 0 {name=l42}
C {noconn.sym} 200 -2680 1 0 {name=l51}
C {sg13g2_pr/ptap1.sym} 1360 350 0 0 {name=R4
model=ptap1
spiceprefix=X
w=3.632e-6
l=3.632e-6
lvs_format="tcleval(@name @pinlist @model A=13.1934p P=84.705u )"
}
C {sg13g2_pr/ptap1.sym} 1260 350 0 0 {name=R1
model=ptap1
spiceprefix=X
w=100.84e-6
l=100.84e-6
lvs_format="tcleval(@name @pinlist @model A=10168.74p P=982.42u )"
}
C {iopin.sym} 70 40 2 0 {name=p48 lab=analog_io[30:10]}
C {iopin.sym} 70 70 2 0 {name=p49 lab=analog_io[7:4]}
C {iopin.sym} 70 100 2 0 {name=p50 lab=analog_io[1:0]}
C {iopin.sym} 220 10 2 0 {name=p51 lab=ui_PAD[31]}
C {iopin.sym} 220 40 2 0 {name=p52 lab=ui_PAD[9]}
C {iopin.sym} 350 10 2 0 {name=p53 lab=uo_PAD[8]}
C {iopin.sym} 350 40 2 0 {name=p54 lab=uo_PAD[3]}
C {iopin.sym} 350 70 2 0 {name=p55 lab=ui_PAD[2]}
C {iopin.sym} 2520 -20 3 1 {name=p56 lab=VSS2}
C {iopin.sym} 2540 -20 3 1 {name=p57 lab=VDD2}
C {iopin.sym} 2560 -20 3 1 {name=p58 lab=IOVDD2}
C {iopin.sym} 2580 -20 3 1 {name=p59 lab=IOVSS2}
C {iopin.sym} 2800 -2400 2 1 {name=p60 lab=VSS3}
C {iopin.sym} 2800 -2420 2 1 {name=p61 lab=VDD3}
C {iopin.sym} 2800 -2440 2 1 {name=p62 lab=IOVDD3}
C {iopin.sym} 2800 -2460 2 1 {name=p63 lab=IOVSS3}
C {iopin.sym} 420 -2680 1 1 {name=p64 lab=VSS4}
C {iopin.sym} 400 -2680 1 1 {name=p65 lab=VDD4}
C {iopin.sym} 380 -2680 1 1 {name=p66 lab=IOVDD4}
C {iopin.sym} 360 -2680 1 1 {name=p67 lab=IOVSS4}
C {iopin.sym} -130 10 2 0 {name=p68 lab=analog_io_padres[29:28]}
C {iopin.sym} -130 40 2 0 {name=p69 lab=analog_io_padres[34:33]}
C {iopin.sym} -130 70 2 0 {name=p70 lab=ui_p2c[31]}
C {lab_wire.sym} 940 -2340 3 0 {name=p71 sig_type=std_logic lab=analog_io_padres[28]	}
C {lab_wire.sym} 1100 -2340 3 0 {name=p72 sig_type=std_logic lab=analog_io_padres[29]	}
C {lab_wire.sym} 1740 -2340 3 0 {name=p74 sig_type=std_logic lab=analog_io_padres[33]	}
C {lab_wire.sym} 1900 -2340 3 0 {name=p75 sig_type=std_logic lab=analog_io_padres[34]	}
C {lab_wire.sym} 1420 -2340 3 0 {name=p76 sig_type=std_logic lab=ui_p2c[31]	}
C {lab_wire.sym} 480 -1940 0 1 {name=p77 sig_type=std_logic lab=uo_c2p[8]	}
C {iopin.sym} -420 10 2 0 {name=p78 lab=ui_p2c[9]}
C {lab_wire.sym} 480 -1620 0 1 {name=p79 sig_type=std_logic lab=analog_io_padres[6]	}
C {lab_wire.sym} 480 -1460 0 1 {name=p80 sig_type=std_logic lab=analog_io_padres[5]	}
C {lab_wire.sym} 480 -1140 0 1 {name=p81 sig_type=std_logic lab=uo_c2p[3]	}
C {lab_wire.sym} 480 -980 0 1 {name=p82 sig_type=std_logic lab=ui_p2c[2]	}
C {lab_wire.sym} 480 -820 0 1 {name=p83 sig_type=std_logic lab=analog_io_padres[1]	}
C {lab_wire.sym} 480 -660 0 1 {name=p84 sig_type=std_logic lab=analog_io_padres[0]	}
C {lab_wire.sym} 620 -360 1 0 {name=p85 sig_type=std_logic lab=ui_p2c[9]	}
C {iopin.sym} -420 40 2 0 {name=p86 lab=ui_p2c[2]}
C {iopin.sym} -420 80 2 0 {name=p87 lab=analog_io_padres[5:6]}
C {iopin.sym} -420 110 2 0 {name=p88 lab=analog_io_padres[0:1]}
C {iopin.sym} -420 140 2 0 {name=p89 lab=uo_c2p[8]}
C {iopin.sym} -420 170 2 0 {name=p90 lab=uo_c2p[3]}
C {sg13g2_Filler4000.sym} 400 660 0 0 {name=x1[0]}
C {sg13g2_Filler1000.sym} 520 660 0 0 {name=x2[0]}
C {sg13g2_Filler400.sym} 640 660 0 0 {name=x3[1:0]}
C {sg13g2_Filler200.sym} 760 660 0 0 {name=x4[0]}
C {sg13g2_Filler4000.sym} 980 660 0 0 {name=x5[10:0]}
C {sg13g2_Filler400.sym} 1100 660 0 0 {name=x6[10:0]}
C {lab_pin.sym} 160 520 0 0 {name=p91 sig_type=std_logic lab=VSS2}
C {lab_pin.sym} 160 540 0 0 {name=p92 sig_type=std_logic lab=VDD2}
C {lab_pin.sym} 160 560 0 0 {name=p93 sig_type=std_logic lab=IOVDD2}
C {lab_pin.sym} 160 580 0 0 {name=p94 sig_type=std_logic lab=IOVSS2}
C {lab_pin.sym} 160 740 0 0 {name=p95 sig_type=std_logic lab=SUB}
C {sg13g2_pr/ptap1.sym} 1360 670 0 0 {name=R2
model=ptap1
spiceprefix=X
w=3.632e-6
l=3.632e-6
lvs_format="tcleval(@name @pinlist @model A=13.1934p P=84.705u )"
}
C {sg13g2_pr/ptap1.sym} 1260 670 0 0 {name=R3
model=ptap1
spiceprefix=X
w=100.84e-6
l=100.84e-6
lvs_format="tcleval(@name @pinlist @model A=10168.74p P=982.42u )"
}
C {sg13g2_Filler4000.sym} 400 980 0 0 {name=x7[0]}
C {sg13g2_Filler1000.sym} 520 980 0 0 {name=x8[2:0]}
C {sg13g2_Filler400.sym} 640 980 0 0 {name=x9[2:0]}
C {sg13g2_Filler200.sym} 760 980 0 0 {name=x10[2:0]}
C {sg13g2_Filler4000.sym} 980 980 0 0 {name=x15[11:0]}
C {sg13g2_Filler400.sym} 1100 980 0 0 {name=x18[11:0]}
C {lab_pin.sym} 160 840 0 0 {name=p96 sig_type=std_logic lab=VSS3}
C {lab_pin.sym} 160 860 0 0 {name=p97 sig_type=std_logic lab=VDD3}
C {lab_pin.sym} 160 880 0 0 {name=p98 sig_type=std_logic lab=IOVDD3}
C {lab_pin.sym} 160 900 0 0 {name=p99 sig_type=std_logic lab=IOVSS3}
C {lab_pin.sym} 160 1060 0 0 {name=p100 sig_type=std_logic lab=SUB}
C {sg13g2_pr/ptap1.sym} 1360 990 0 0 {name=R5
model=ptap1
spiceprefix=X
w=3.632e-6
l=3.632e-6
lvs_format="tcleval(@name @pinlist @model A=13.1934p P=84.705u )"
}
C {sg13g2_pr/ptap1.sym} 1260 990 0 0 {name=R6
model=ptap1
spiceprefix=X
w=100.84e-6
l=100.84e-6
lvs_format="tcleval(@name @pinlist @model A=10168.74p P=982.42u )"
}
C {sg13g2_Filler4000.sym} 400 1300 0 0 {name=x19[0]}
C {sg13g2_Filler1000.sym} 520 1300 0 0 {name=x20[1:0]}
C {sg13g2_Filler400.sym} 640 1300 0 0 {name=x21[1:0]}
C {sg13g2_Filler200.sym} 760 1300 0 0 {name=x22[1:0]}
C {sg13g2_Filler4000.sym} 980 1300 0 0 {name=x23[11:0]}
C {sg13g2_Filler400.sym} 1100 1300 0 0 {name=x24[11:0]}
C {lab_pin.sym} 160 1160 0 0 {name=p101 sig_type=std_logic lab=VSS4}
C {lab_pin.sym} 160 1180 0 0 {name=p102 sig_type=std_logic lab=VDD4}
C {lab_pin.sym} 160 1200 0 0 {name=p103 sig_type=std_logic lab=IOVDD4}
C {lab_pin.sym} 160 1220 0 0 {name=p104 sig_type=std_logic lab=IOVSS4}
C {lab_pin.sym} 160 1380 0 0 {name=p105 sig_type=std_logic lab=SUB}
C {sg13g2_pr/ptap1.sym} 1360 1310 0 0 {name=R7
model=ptap1
spiceprefix=X
w=3.632e-6
l=3.632e-6
lvs_format="tcleval(@name @pinlist @model A=13.1934p P=84.705u )"
}
C {sg13g2_pr/ptap1.sym} 1260 1310 0 0 {name=R8
model=ptap1
spiceprefix=X
w=100.84e-6
l=100.84e-6
lvs_format="tcleval(@name @pinlist @model A=10168.74p P=982.42u )"
}
C {lab_wire.sym} 2460 -1880 0 0 {name=p73 sig_type=std_logic lab=analog_io_padres[25]	}
C {lab_wire.sym} 2460 -1400 0 0 {name=p106 sig_type=std_logic lab=analog_io_padres[22]	}
C {lab_wire.sym} 2460 -920 0 0 {name=p107 sig_type=std_logic lab=analog_io_padres[19]	}
C {iopin.sym} -420 210 2 0 {name=p108 lab=analog_io_padres[19]}
C {iopin.sym} -420 240 2 0 {name=p109 lab=analog_io_padres[22]}
C {iopin.sym} -420 270 2 0 {name=p110 lab=analog_io_padres[25]}
C {lab_pin.sym} 1040 -360 1 0 {name=p111 sig_type=std_logic lab=analog_io_padres[10]}
C {lab_pin.sym} 1200 -360 1 0 {name=p112 sig_type=std_logic lab=analog_io_padres[11]}
C {lab_pin.sym} 1360 -360 1 0 {name=p113 sig_type=std_logic lab=analog_io_padres[12]}
C {lab_pin.sym} 1520 -360 1 0 {name=p114 sig_type=std_logic lab=analog_io_padres[13]}
C {lab_pin.sym} 1680 -360 1 0 {name=p115 sig_type=std_logic lab=analog_io_padres[14]}
C {lab_pin.sym} 1840 -360 1 0 {name=p116 sig_type=std_logic lab=analog_io_padres[15]}
C {lab_pin.sym} 2000 -360 1 0 {name=p117 sig_type=std_logic lab=analog_io_padres[16]}
C {lab_pin.sym} 2160 -360 1 0 {name=p118 sig_type=std_logic lab=analog_io_padres[17]}
